VERSION 5.8 ;
BUSBITCHARS "[]" ;

UNITS
  DATABASE MICRONS 1000 ;
END UNITS

PROPERTYDEFINITIONS
  MACRO expanded_util REAL ;
  MACRO achieved_target_routing_density REAL ;
END PROPERTYDEFINITIONS

LAYER OVERLAP
  TYPE OVERLAP ;
END OVERLAP

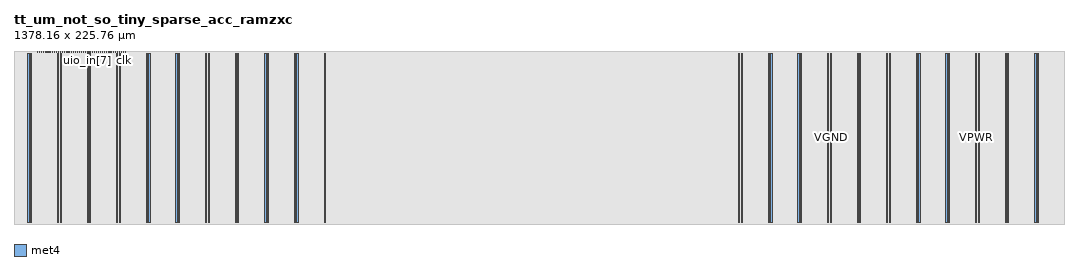
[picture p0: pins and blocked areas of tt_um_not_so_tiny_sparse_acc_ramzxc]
MACRO tt_um_not_so_tiny_sparse_acc_ramzxc
  CLASS BLOCK ;
  ORIGIN 0 0 ;
  SIZE 1378.16 BY 225.76 ;
  SYMMETRY X Y ;
  PIN ui_in[7]
    DIRECTION INPUT ;
    USE SIGNAL ;
    PORT
      LAYER met4 ;
        RECT 118.99 224.76 119.29 225.76 ;
    END
    ANTENNAPARTIALMETALAREA 0 ;
    ANTENNAPARTIALMETALSIDEAREA 0 ;
  END ui_in[7]
  PIN ui_in[6]
    DIRECTION INPUT ;
    USE SIGNAL ;
    PORT
      LAYER met4 ;
        RECT 121.75 224.76 122.05 225.76 ;
    END
    ANTENNAPARTIALMETALAREA 0 ;
    ANTENNAPARTIALMETALSIDEAREA 0 ;
  END ui_in[6]
  PIN ui_in[5]
    DIRECTION INPUT ;
    USE SIGNAL ;
    PORT
      LAYER met4 ;
        RECT 124.51 224.76 124.81 225.76 ;
    END
    ANTENNAPARTIALMETALAREA 0 ;
    ANTENNAPARTIALMETALSIDEAREA 0 ;
  END ui_in[5]
  PIN ui_in[4]
    DIRECTION INPUT ;
    USE SIGNAL ;
    PORT
      LAYER met4 ;
        RECT 127.27 224.76 127.57 225.76 ;
    END
    ANTENNAPARTIALMETALAREA 0 ;
    ANTENNAPARTIALMETALSIDEAREA 0 ;
  END ui_in[4]
  PIN ui_in[3]
    DIRECTION INPUT ;
    USE SIGNAL ;
    PORT
      LAYER met4 ;
        RECT 130.03 224.76 130.33 225.76 ;
    END
    ANTENNAPARTIALMETALAREA 0 ;
    ANTENNAPARTIALMETALSIDEAREA 0 ;
  END ui_in[3]
  PIN ui_in[2]
    DIRECTION INPUT ;
    USE SIGNAL ;
    PORT
      LAYER met4 ;
        RECT 132.79 224.76 133.09 225.76 ;
    END
    ANTENNAPARTIALMETALAREA 0 ;
    ANTENNAPARTIALMETALSIDEAREA 0 ;
  END ui_in[2]
  PIN ui_in[1]
    DIRECTION INPUT ;
    USE SIGNAL ;
    PORT
      LAYER met4 ;
        RECT 135.55 224.76 135.85 225.76 ;
    END
    ANTENNAPARTIALMETALAREA 0 ;
    ANTENNAPARTIALMETALSIDEAREA 0 ;
  END ui_in[1]
  PIN ui_in[0]
    DIRECTION INPUT ;
    USE SIGNAL ;
    PORT
      LAYER met4 ;
        RECT 138.31 224.76 138.61 225.76 ;
    END
    ANTENNAPARTIALMETALAREA 0 ;
    ANTENNAPARTIALMETALSIDEAREA 0 ;
  END ui_in[0]
  PIN uo_out[7]
    DIRECTION OUTPUT ;
    USE SIGNAL ;
    PORT
      LAYER met4 ;
        RECT 74.83 224.76 75.13 225.76 ;
    END
    ANTENNAPARTIALMETALAREA 0 ;
    ANTENNAPARTIALMETALSIDEAREA 0 ;
  END uo_out[7]
  PIN uo_out[6]
    DIRECTION OUTPUT ;
    USE SIGNAL ;
    PORT
      LAYER met4 ;
        RECT 77.59 224.76 77.89 225.76 ;
    END
    ANTENNAPARTIALMETALAREA 0 ;
    ANTENNAPARTIALMETALSIDEAREA 0 ;
  END uo_out[6]
  PIN uo_out[5]
    DIRECTION OUTPUT ;
    USE SIGNAL ;
    PORT
      LAYER met4 ;
        RECT 80.35 224.76 80.65 225.76 ;
    END
    ANTENNAPARTIALMETALAREA 0 ;
    ANTENNAPARTIALMETALSIDEAREA 0 ;
  END uo_out[5]
  PIN uo_out[4]
    DIRECTION OUTPUT ;
    USE SIGNAL ;
    PORT
      LAYER met4 ;
        RECT 83.11 224.76 83.41 225.76 ;
    END
    ANTENNAPARTIALMETALAREA 0 ;
    ANTENNAPARTIALMETALSIDEAREA 0 ;
  END uo_out[4]
  PIN uo_out[3]
    DIRECTION OUTPUT ;
    USE SIGNAL ;
    PORT
      LAYER met4 ;
        RECT 85.87 224.76 86.17 225.76 ;
    END
    ANTENNAPARTIALMETALAREA 0 ;
    ANTENNAPARTIALMETALSIDEAREA 0 ;
  END uo_out[3]
  PIN uo_out[2]
    DIRECTION OUTPUT ;
    USE SIGNAL ;
    PORT
      LAYER met4 ;
        RECT 88.63 224.76 88.93 225.76 ;
    END
    ANTENNAPARTIALMETALAREA 0 ;
    ANTENNAPARTIALMETALSIDEAREA 0 ;
  END uo_out[2]
  PIN uo_out[1]
    DIRECTION OUTPUT ;
    USE SIGNAL ;
    PORT
      LAYER met4 ;
        RECT 91.39 224.76 91.69 225.76 ;
    END
    ANTENNAPARTIALMETALAREA 0 ;
    ANTENNAPARTIALMETALSIDEAREA 0 ;
  END uo_out[1]
  PIN uo_out[0]
    DIRECTION OUTPUT ;
    USE SIGNAL ;
    PORT
      LAYER met4 ;
        RECT 94.15 224.76 94.45 225.76 ;
    END
    ANTENNAPARTIALMETALAREA 0 ;
    ANTENNAPARTIALMETALSIDEAREA 0 ;
  END uo_out[0]
  PIN uio_in[7]
    DIRECTION INPUT ;
    USE SIGNAL ;
    PORT
      LAYER met4 ;
        RECT 96.91 224.76 97.21 225.76 ;
    END
    ANTENNAPARTIALMETALAREA 0 ;
    ANTENNAPARTIALMETALSIDEAREA 0 ;
  END uio_in[7]
  PIN uio_in[6]
    DIRECTION INPUT ;
    USE SIGNAL ;
    PORT
      LAYER met4 ;
        RECT 99.67 224.76 99.97 225.76 ;
    END
    ANTENNAPARTIALMETALAREA 0 ;
    ANTENNAPARTIALMETALSIDEAREA 0 ;
  END uio_in[6]
  PIN uio_in[5]
    DIRECTION INPUT ;
    USE SIGNAL ;
    PORT
      LAYER met4 ;
        RECT 102.43 224.76 102.73 225.76 ;
    END
    ANTENNAPARTIALMETALAREA 0 ;
    ANTENNAPARTIALMETALSIDEAREA 0 ;
  END uio_in[5]
  PIN uio_in[4]
    DIRECTION INPUT ;
    USE SIGNAL ;
    PORT
      LAYER met4 ;
        RECT 105.19 224.76 105.49 225.76 ;
    END
    ANTENNAPARTIALMETALAREA 0 ;
    ANTENNAPARTIALMETALSIDEAREA 0 ;
  END uio_in[4]
  PIN uio_in[3]
    DIRECTION INPUT ;
    USE SIGNAL ;
    PORT
      LAYER met4 ;
        RECT 107.95 224.76 108.25 225.76 ;
    END
    ANTENNAPARTIALMETALAREA 0 ;
    ANTENNAPARTIALMETALSIDEAREA 0 ;
  END uio_in[3]
  PIN uio_in[2]
    DIRECTION INPUT ;
    USE SIGNAL ;
    PORT
      LAYER met4 ;
        RECT 110.71 224.76 111.01 225.76 ;
    END
    ANTENNAPARTIALMETALAREA 0 ;
    ANTENNAPARTIALMETALSIDEAREA 0 ;
  END uio_in[2]
  PIN uio_in[1]
    DIRECTION INPUT ;
    USE SIGNAL ;
    PORT
      LAYER met4 ;
        RECT 113.47 224.76 113.77 225.76 ;
    END
    ANTENNAPARTIALMETALAREA 0 ;
    ANTENNAPARTIALMETALSIDEAREA 0 ;
  END uio_in[1]
  PIN uio_in[0]
    DIRECTION INPUT ;
    USE SIGNAL ;
    PORT
      LAYER met4 ;
        RECT 116.23 224.76 116.53 225.76 ;
    END
    ANTENNAPARTIALMETALAREA 0 ;
    ANTENNAPARTIALMETALSIDEAREA 0 ;
  END uio_in[0]
  PIN uio_out[7]
    DIRECTION OUTPUT ;
    USE SIGNAL ;
    PORT
      LAYER met4 ;
        RECT 52.75 224.76 53.05 225.76 ;
    END
    ANTENNAPARTIALMETALAREA 0 ;
    ANTENNAPARTIALMETALSIDEAREA 0 ;
  END uio_out[7]
  PIN uio_out[6]
    DIRECTION OUTPUT ;
    USE SIGNAL ;
    PORT
      LAYER met4 ;
        RECT 55.51 224.76 55.81 225.76 ;
    END
    ANTENNAPARTIALMETALAREA 0 ;
    ANTENNAPARTIALMETALSIDEAREA 0 ;
  END uio_out[6]
  PIN uio_out[5]
    DIRECTION OUTPUT ;
    USE SIGNAL ;
    PORT
      LAYER met4 ;
        RECT 58.27 224.76 58.57 225.76 ;
    END
    ANTENNAPARTIALMETALAREA 0 ;
    ANTENNAPARTIALMETALSIDEAREA 0 ;
  END uio_out[5]
  PIN uio_out[4]
    DIRECTION OUTPUT ;
    USE SIGNAL ;
    PORT
      LAYER met4 ;
        RECT 61.03 224.76 61.33 225.76 ;
    END
    ANTENNAPARTIALMETALAREA 0 ;
    ANTENNAPARTIALMETALSIDEAREA 0 ;
  END uio_out[4]
  PIN uio_out[3]
    DIRECTION OUTPUT ;
    USE SIGNAL ;
    PORT
      LAYER met4 ;
        RECT 63.79 224.76 64.09 225.76 ;
    END
    ANTENNAPARTIALMETALAREA 0 ;
    ANTENNAPARTIALMETALSIDEAREA 0 ;
  END uio_out[3]
  PIN uio_out[2]
    DIRECTION OUTPUT ;
    USE SIGNAL ;
    PORT
      LAYER met4 ;
        RECT 66.55 224.76 66.85 225.76 ;
    END
    ANTENNAPARTIALMETALAREA 0 ;
    ANTENNAPARTIALMETALSIDEAREA 0 ;
  END uio_out[2]
  PIN uio_out[1]
    DIRECTION OUTPUT ;
    USE SIGNAL ;
    PORT
      LAYER met4 ;
        RECT 69.31 224.76 69.61 225.76 ;
    END
    ANTENNAPARTIALMETALAREA 0 ;
    ANTENNAPARTIALMETALSIDEAREA 0 ;
  END uio_out[1]
  PIN uio_out[0]
    DIRECTION OUTPUT ;
    USE SIGNAL ;
    PORT
      LAYER met4 ;
        RECT 72.07 224.76 72.37 225.76 ;
    END
    ANTENNAPARTIALMETALAREA 0 ;
    ANTENNAPARTIALMETALSIDEAREA 0 ;
  END uio_out[0]
  PIN uio_oe[7]
    DIRECTION OUTPUT ;
    USE SIGNAL ;
    PORT
      LAYER met4 ;
        RECT 30.67 224.76 30.97 225.76 ;
    END
    ANTENNAPARTIALMETALAREA 0 ;
    ANTENNAPARTIALMETALSIDEAREA 0 ;
  END uio_oe[7]
  PIN uio_oe[6]
    DIRECTION OUTPUT ;
    USE SIGNAL ;
    PORT
      LAYER met4 ;
        RECT 33.43 224.76 33.73 225.76 ;
    END
    ANTENNAPARTIALMETALAREA 0 ;
    ANTENNAPARTIALMETALSIDEAREA 0 ;
  END uio_oe[6]
  PIN uio_oe[5]
    DIRECTION OUTPUT ;
    USE SIGNAL ;
    PORT
      LAYER met4 ;
        RECT 36.19 224.76 36.49 225.76 ;
    END
    ANTENNAPARTIALMETALAREA 0 ;
    ANTENNAPARTIALMETALSIDEAREA 0 ;
  END uio_oe[5]
  PIN uio_oe[4]
    DIRECTION OUTPUT ;
    USE SIGNAL ;
    PORT
      LAYER met4 ;
        RECT 38.95 224.76 39.25 225.76 ;
    END
    ANTENNAPARTIALMETALAREA 0 ;
    ANTENNAPARTIALMETALSIDEAREA 0 ;
  END uio_oe[4]
  PIN uio_oe[3]
    DIRECTION OUTPUT ;
    USE SIGNAL ;
    PORT
      LAYER met4 ;
        RECT 41.71 224.76 42.01 225.76 ;
    END
    ANTENNAPARTIALMETALAREA 0 ;
    ANTENNAPARTIALMETALSIDEAREA 0 ;
  END uio_oe[3]
  PIN uio_oe[2]
    DIRECTION OUTPUT ;
    USE SIGNAL ;
    PORT
      LAYER met4 ;
        RECT 44.47 224.76 44.77 225.76 ;
    END
    ANTENNAPARTIALMETALAREA 0 ;
    ANTENNAPARTIALMETALSIDEAREA 0 ;
  END uio_oe[2]
  PIN uio_oe[1]
    DIRECTION OUTPUT ;
    USE SIGNAL ;
    PORT
      LAYER met4 ;
        RECT 47.23 224.76 47.53 225.76 ;
    END
    ANTENNAPARTIALMETALAREA 0 ;
    ANTENNAPARTIALMETALSIDEAREA 0 ;
  END uio_oe[1]
  PIN uio_oe[0]
    DIRECTION OUTPUT ;
    USE SIGNAL ;
    PORT
      LAYER met4 ;
        RECT 49.99 224.76 50.29 225.76 ;
    END
    ANTENNAPARTIALMETALAREA 0 ;
    ANTENNAPARTIALMETALSIDEAREA 0 ;
  END uio_oe[0]
  PIN ena
    DIRECTION INPUT ;
    USE SIGNAL ;
    PORT
      LAYER met4 ;
        RECT 146.59 224.76 146.89 225.76 ;
    END
    ANTENNAPARTIALMETALAREA 0 ;
    ANTENNAPARTIALMETALSIDEAREA 0 ;
  END ena
  PIN clk
    DIRECTION INPUT ;
    USE CLOCK ;
    PORT
      LAYER met4 ;
        RECT 143.83 224.76 144.13 225.76 ;
    END
    ANTENNAPARTIALMETALAREA 0 ;
    ANTENNAPARTIALMETALSIDEAREA 0 ;
  END clk
  PIN rst_n
    DIRECTION INPUT ;
    USE SIGNAL ;
    PORT
      LAYER met4 ;
        RECT 141.07 224.76 141.37 225.76 ;
    END
    ANTENNAPARTIALMETALAREA 0 ;
    ANTENNAPARTIALMETALSIDEAREA 0 ;
  END rst_n
  PIN VPWR
    DIRECTION INPUT ;
    USE POWER ;
    PORT
      LAYER met4 ;
        RECT 18.28 2.48 19.88 223.28 ;
        RECT 57.15 2.48 58.75 223.28 ;
        RECT 96.02 2.48 97.62 223.28 ;
        RECT 134.89 2.48 136.49 223.28 ;
        RECT 173.76 2.48 175.36 223.28 ;
        RECT 212.63 2.48 214.23 223.28 ;
        RECT 251.5 2.48 253.1 223.28 ;
        RECT 290.37 2.48 291.97 223.28 ;
        RECT 329.24 2.48 330.84 223.28 ;
        RECT 368.11 2.48 369.71 223.28 ;
        RECT 406.98 2.48 408.58 223.28 ;
        RECT 951.16 2.48 952.76 223.28 ;
        RECT 990.03 2.48 991.63 223.28 ;
        RECT 1028.9 2.48 1030.5 223.28 ;
        RECT 1067.77 2.48 1069.37 223.28 ;
        RECT 1106.64 2.48 1108.24 223.28 ;
        RECT 1145.51 2.48 1147.11 223.28 ;
        RECT 1184.38 2.48 1185.98 223.28 ;
        RECT 1223.25 2.48 1224.85 223.28 ;
        RECT 1262.12 2.48 1263.72 223.28 ;
        RECT 1300.99 2.48 1302.59 223.28 ;
        RECT 1339.86 2.48 1341.46 223.28 ;
    END
    ANTENNAPARTIALMETALAREA 0 ;
    ANTENNAPARTIALMETALSIDEAREA 0 ;
  END VPWR
  PIN VGND
    DIRECTION INPUT ;
    USE GROUND ;
    PORT
      LAYER met4 ;
        RECT 21.58 2.48 23.18 223.28 ;
        RECT 60.45 2.48 62.05 223.28 ;
        RECT 99.32 2.48 100.92 223.28 ;
        RECT 138.19 2.48 139.79 223.28 ;
        RECT 177.06 2.48 178.66 223.28 ;
        RECT 215.93 2.48 217.53 223.28 ;
        RECT 254.8 2.48 256.4 223.28 ;
        RECT 293.67 2.48 295.27 223.28 ;
        RECT 332.54 2.48 334.14 223.28 ;
        RECT 371.41 2.48 373.01 223.28 ;
        RECT 954.46 2.48 956.06 223.28 ;
        RECT 993.33 2.48 994.93 223.28 ;
        RECT 1032.2 2.48 1033.8 223.28 ;
        RECT 1071.07 2.48 1072.67 223.28 ;
        RECT 1109.94 2.48 1111.54 223.28 ;
        RECT 1148.81 2.48 1150.41 223.28 ;
        RECT 1187.68 2.48 1189.28 223.28 ;
        RECT 1226.55 2.48 1228.15 223.28 ;
        RECT 1265.42 2.48 1267.02 223.28 ;
        RECT 1304.29 2.48 1305.89 223.28 ;
        RECT 1343.16 2.48 1344.76 223.28 ;
    END
    ANTENNAPARTIALMETALAREA 0 ;
    ANTENNAPARTIALMETALSIDEAREA 0 ;
  END VGND
  OBS
    LAYER li1 ;
      RECT 331.2 0 629.28 225.76 ;
      RECT 11.96 0 310.04 225.76 ;
    LAYER li1 SPACING 0 ;
      RECT 0 0 1378.16 225.76 ;
    LAYER met1 SPACING 0 ;
      RECT 0 0 1378.16 225.76 ;
    LAYER met2 SPACING 0 ;
      RECT 0 0 1378.16 225.76 ;
    LAYER met3 SPACING 0 ;
      RECT 0 0 1378.16 225.76 ;
    LAYER met4 SPACING 0 ;
      POLYGON 1378.16 225.76 1378.16 223.28 18.28 223.28 18.28 2.48 19.88 2.48 19.88 223.28 21.58 223.28 21.58 2.48 23.18 2.48 23.18 223.28 57.15 223.28 57.15 2.48 58.75 2.48 58.75 223.28 60.45 223.28 60.45 2.48 62.05 2.48 62.05 223.28 96.02 223.28 96.02 2.48 97.62 2.48 97.62 223.28 99.32 223.28 99.32 2.48 100.92 2.48 100.92 223.28 134.89 223.28 134.89 2.48 136.49 2.48 136.49 223.28 138.19 223.28 138.19 2.48 139.79 2.48 139.79 223.28 173.76 223.28 173.76 2.48 175.36 2.48 175.36 223.28 177.06 223.28 177.06 2.48 178.66 2.48 178.66 223.28 212.63 223.28 212.63 2.48 214.23 2.48 214.23 223.28 215.93 223.28 215.93 2.48 217.53 2.48 217.53 223.28 251.5 223.28 251.5 2.48 253.1 2.48 253.1 223.28 254.8 223.28 254.8 2.48 256.4 2.48 256.4 223.28 290.37 223.28 290.37 2.48 291.97 2.48 291.97 223.28 293.67 223.28 293.67 2.48 295.27 2.48 295.27 223.28 329.24 223.28 329.24 2.48 330.84 2.48 330.84 223.28 332.54 223.28 332.54 2.48 334.14 2.48 334.14 223.28 368.11 223.28 368.11 2.48 369.71 2.48 369.71 223.28 371.41 223.28 371.41 2.48 373.01 2.48 373.01 223.28 406.98 223.28 406.98 2.48 408.58 2.48 408.58 223.28 951.16 223.28 951.16 2.48 952.76 2.48 952.76 223.28 954.46 223.28 954.46 2.48 956.06 2.48 956.06 223.28 990.03 223.28 990.03 2.48 991.63 2.48 991.63 223.28 993.33 223.28 993.33 2.48 994.93 2.48 994.93 223.28 1028.9 223.28 1028.9 2.48 1030.5 2.48 1030.5 223.28 1032.2 223.28 1032.2 2.48 1033.8 2.48 1033.8 223.28 1067.77 223.28 1067.77 2.48 1069.37 2.48 1069.37 223.28 1071.07 223.28 1071.07 2.48 1072.67 2.48 1072.67 223.28 1106.64 223.28 1106.64 2.48 1108.24 2.48 1108.24 223.28 1109.94 223.28 1109.94 2.48 1111.54 2.48 1111.54 223.28 1145.51 223.28 1145.51 2.48 1147.11 2.48 1147.11 223.28 1148.81 223.28 1148.81 2.48 1150.41 2.48 1150.41 223.28 1184.38 223.28 1184.38 2.48 1185.98 2.48 1185.98 223.28 1187.68 223.28 1187.68 2.48 1189.28 2.48 1189.28 223.28 1223.25 223.28 1223.25 2.48 1224.85 2.48 1224.85 223.28 1226.55 223.28 1226.55 2.48 1228.15 2.48 1228.15 223.28 1262.12 223.28 1262.12 2.48 1263.72 2.48 1263.72 223.28 1265.42 223.28 1265.42 2.48 1267.02 2.48 1267.02 223.28 1300.99 223.28 1300.99 2.48 1302.59 2.48 1302.59 223.28 1304.29 223.28 1304.29 2.48 1305.89 2.48 1305.89 223.28 1339.86 223.28 1339.86 2.48 1341.46 2.48 1341.46 223.28 1343.16 223.28 1343.16 2.48 1344.76 2.48 1344.76 223.28 1378.16 223.28 1378.16 0 0 0 0 225.76 30.67 225.76 30.67 224.76 30.97 224.76 30.97 225.76 33.43 225.76 33.43 224.76 33.73 224.76 33.73 225.76 36.19 225.76 36.19 224.76 36.49 224.76 36.49 225.76 38.95 225.76 38.95 224.76 39.25 224.76 39.25 225.76 41.71 225.76 41.71 224.76 42.01 224.76 42.01 225.76 44.47 225.76 44.47 224.76 44.77 224.76 44.77 225.76 47.23 225.76 47.23 224.76 47.53 224.76 47.53 225.76 49.99 225.76 49.99 224.76 50.29 224.76 50.29 225.76 52.75 225.76 52.75 224.76 53.05 224.76 53.05 225.76 55.51 225.76 55.51 224.76 55.81 224.76 55.81 225.76 58.27 225.76 58.27 224.76 58.57 224.76 58.57 225.76 61.03 225.76 61.03 224.76 61.33 224.76 61.33 225.76 63.79 225.76 63.79 224.76 64.09 224.76 64.09 225.76 66.55 225.76 66.55 224.76 66.85 224.76 66.85 225.76 69.31 225.76 69.31 224.76 69.61 224.76 69.61 225.76 72.07 225.76 72.07 224.76 72.37 224.76 72.37 225.76 74.83 225.76 74.83 224.76 75.13 224.76 75.13 225.76 77.59 225.76 77.59 224.76 77.89 224.76 77.89 225.76 80.35 225.76 80.35 224.76 80.65 224.76 80.65 225.76 83.11 225.76 83.11 224.76 83.41 224.76 83.41 225.76 85.87 225.76 85.87 224.76 86.17 224.76 86.17 225.76 88.63 225.76 88.63 224.76 88.93 224.76 88.93 225.76 91.39 225.76 91.39 224.76 91.69 224.76 91.69 225.76 94.15 225.76 94.15 224.76 94.45 224.76 94.45 225.76 96.91 225.76 96.91 224.76 97.21 224.76 97.21 225.76 99.67 225.76 99.67 224.76 99.97 224.76 99.97 225.76 102.43 225.76 102.43 224.76 102.73 224.76 102.73 225.76 105.19 225.76 105.19 224.76 105.49 224.76 105.49 225.76 107.95 225.76 107.95 224.76 108.25 224.76 108.25 225.76 110.71 225.76 110.71 224.76 111.01 224.76 111.01 225.76 113.47 225.76 113.47 224.76 113.77 224.76 113.77 225.76 116.23 225.76 116.23 224.76 116.53 224.76 116.53 225.76 118.99 225.76 118.99 224.76 119.29 224.76 119.29 225.76 121.75 225.76 121.75 224.76 122.05 224.76 122.05 225.76 124.51 225.76 124.51 224.76 124.81 224.76 124.81 225.76 127.27 225.76 127.27 224.76 127.57 224.76 127.57 225.76 130.03 225.76 130.03 224.76 130.33 224.76 130.33 225.76 132.79 225.76 132.79 224.76 133.09 224.76 133.09 225.76 135.55 225.76 135.55 224.76 135.85 224.76 135.85 225.76 138.31 225.76 138.31 224.76 138.61 224.76 138.61 225.76 141.07 225.76 141.07 224.76 141.37 224.76 141.37 225.76 143.83 225.76 143.83 224.76 144.13 224.76 144.13 225.76 146.59 225.76 146.59 224.76 146.89 224.76 146.89 225.76 ;
    LAYER nwell SPACING 0 ;
      RECT 0 0 1378.16 225.76 ;
    LAYER pwell SPACING 0 ;
      RECT 0 0 1378.16 225.76 ;
    LAYER met4 ;
      POLYGON 61.75 224.91 61.75 224.59 62.67 224.59 62.67 221.205 62.685 221.205 62.685 220.875 62.355 220.875 62.355 221.205 62.37 221.205 62.37 224.29 61.45 224.29 61.45 224.36 61.73 224.36 61.73 224.91 ;
      RECT 1069.755 193.675 1070.085 194.005 ;
      RECT 1069.755 190.955 1070.085 191.285 ;
      POLYGON 1151.045 178.365 1151.045 178.035 1151.03 178.035 1151.03 142.325 1151.045 142.325 1151.045 141.995 1150.715 141.995 1150.715 142.325 1150.73 142.325 1150.73 178.035 1150.715 178.035 1150.715 178.365 ;
      RECT 1069.755 173.275 1070.085 173.605 ;
      RECT 1069.755 171.915 1070.085 172.245 ;
      POLYGON 1151.045 136.885 1151.045 136.555 1151.03 136.555 1151.03 115.805 1151.045 115.805 1151.045 115.475 1150.715 115.475 1150.715 115.805 1150.73 115.805 1150.73 136.555 1150.715 136.555 1150.715 136.885 ;
      POLYGON 995.565 136.885 995.565 136.87 998.31 136.87 998.31 136.57 995.565 136.57 995.565 136.555 995.235 136.555 995.235 136.885 ;
      POLYGON 1151.045 98.805 1151.045 98.475 1151.03 98.475 1151.03 88.605 1151.045 88.605 1151.045 88.275 1150.715 88.275 1150.715 88.605 1150.73 88.605 1150.73 98.475 1150.715 98.475 1150.715 98.805 ;
      POLYGON 1377.76 225.36 1377.76 223.68 17.88 223.68 17.88 2.08 20.28 2.08 20.28 223.68 21.18 223.68 21.18 2.08 23.58 2.08 23.58 223.68 56.75 223.68 56.75 2.08 59.15 2.08 59.15 223.68 60.05 223.68 60.05 2.08 62.45 2.08 62.45 223.68 95.62 223.68 95.62 2.08 98.02 2.08 98.02 223.68 98.92 223.68 98.92 2.08 101.32 2.08 101.32 223.68 134.49 223.68 134.49 2.08 136.89 2.08 136.89 223.68 137.79 223.68 137.79 2.08 140.19 2.08 140.19 223.68 173.36 223.68 173.36 2.08 175.76 2.08 175.76 223.68 176.66 223.68 176.66 2.08 179.06 2.08 179.06 223.68 212.23 223.68 212.23 2.08 214.63 2.08 214.63 223.68 215.53 223.68 215.53 2.08 217.93 2.08 217.93 223.68 251.1 223.68 251.1 2.08 253.5 2.08 253.5 223.68 254.4 223.68 254.4 2.08 256.8 2.08 256.8 223.68 289.97 223.68 289.97 2.08 292.37 2.08 292.37 223.68 293.27 223.68 293.27 2.08 295.67 2.08 295.67 223.68 328.84 223.68 328.84 2.08 331.24 2.08 331.24 223.68 332.14 223.68 332.14 2.08 334.54 2.08 334.54 223.68 367.71 223.68 367.71 2.08 370.11 2.08 370.11 223.68 371.01 223.68 371.01 2.08 373.41 2.08 373.41 223.68 406.58 223.68 406.58 2.08 408.98 2.08 408.98 223.68 950.76 223.68 950.76 2.08 953.16 2.08 953.16 223.68 954.06 223.68 954.06 2.08 956.46 2.08 956.46 223.68 989.63 223.68 989.63 2.08 992.03 2.08 992.03 223.68 992.93 223.68 992.93 2.08 995.33 2.08 995.33 223.68 1028.5 223.68 1028.5 2.08 1030.9 2.08 1030.9 223.68 1031.8 223.68 1031.8 2.08 1034.2 2.08 1034.2 223.68 1067.37 223.68 1067.37 2.08 1069.77 2.08 1069.77 223.68 1070.67 223.68 1070.67 2.08 1073.07 2.08 1073.07 223.68 1106.24 223.68 1106.24 2.08 1108.64 2.08 1108.64 223.68 1109.54 223.68 1109.54 2.08 1111.94 2.08 1111.94 223.68 1145.11 223.68 1145.11 2.08 1147.51 2.08 1147.51 223.68 1148.41 223.68 1148.41 2.08 1150.81 2.08 1150.81 223.68 1183.98 223.68 1183.98 2.08 1186.38 2.08 1186.38 223.68 1187.28 223.68 1187.28 2.08 1189.68 2.08 1189.68 223.68 1222.85 223.68 1222.85 2.08 1225.25 2.08 1225.25 223.68 1226.15 223.68 1226.15 2.08 1228.55 2.08 1228.55 223.68 1261.72 223.68 1261.72 2.08 1264.12 2.08 1264.12 223.68 1265.02 223.68 1265.02 2.08 1267.42 2.08 1267.42 223.68 1300.59 223.68 1300.59 2.08 1302.99 2.08 1302.99 223.68 1303.89 223.68 1303.89 2.08 1306.29 2.08 1306.29 223.68 1339.46 223.68 1339.46 2.08 1341.86 2.08 1341.86 223.68 1342.76 223.68 1342.76 2.08 1345.16 2.08 1345.16 223.68 1377.76 223.68 1377.76 0.4 0.4 0.4 0.4 225.36 30.27 225.36 30.27 224.36 31.37 224.36 31.37 225.36 33.03 225.36 33.03 224.36 34.13 224.36 34.13 225.36 35.79 225.36 35.79 224.36 36.89 224.36 36.89 225.36 38.55 225.36 38.55 224.36 39.65 224.36 39.65 225.36 41.31 225.36 41.31 224.36 42.41 224.36 42.41 225.36 44.07 225.36 44.07 224.36 45.17 224.36 45.17 225.36 46.83 225.36 46.83 224.36 47.93 224.36 47.93 225.36 49.59 225.36 49.59 224.36 50.69 224.36 50.69 225.36 52.35 225.36 52.35 224.36 53.45 224.36 53.45 225.36 55.11 225.36 55.11 224.36 56.21 224.36 56.21 225.36 57.87 225.36 57.87 224.36 58.97 224.36 58.97 225.36 60.63 225.36 60.63 224.36 61.73 224.36 61.73 225.36 63.39 225.36 63.39 224.36 64.49 224.36 64.49 225.36 66.15 225.36 66.15 224.36 67.25 224.36 67.25 225.36 68.91 225.36 68.91 224.36 70.01 224.36 70.01 225.36 71.67 225.36 71.67 224.36 72.77 224.36 72.77 225.36 74.43 225.36 74.43 224.36 75.53 224.36 75.53 225.36 77.19 225.36 77.19 224.36 78.29 224.36 78.29 225.36 79.95 225.36 79.95 224.36 81.05 224.36 81.05 225.36 82.71 225.36 82.71 224.36 83.81 224.36 83.81 225.36 85.47 225.36 85.47 224.36 86.57 224.36 86.57 225.36 88.23 225.36 88.23 224.36 89.33 224.36 89.33 225.36 90.99 225.36 90.99 224.36 92.09 224.36 92.09 225.36 93.75 225.36 93.75 224.36 94.85 224.36 94.85 225.36 96.51 225.36 96.51 224.36 97.61 224.36 97.61 225.36 99.27 225.36 99.27 224.36 100.37 224.36 100.37 225.36 102.03 225.36 102.03 224.36 103.13 224.36 103.13 225.36 104.79 225.36 104.79 224.36 105.89 224.36 105.89 225.36 107.55 225.36 107.55 224.36 108.65 224.36 108.65 225.36 110.31 225.36 110.31 224.36 111.41 224.36 111.41 225.36 113.07 225.36 113.07 224.36 114.17 224.36 114.17 225.36 115.83 225.36 115.83 224.36 116.93 224.36 116.93 225.36 118.59 225.36 118.59 224.36 119.69 224.36 119.69 225.36 121.35 225.36 121.35 224.36 122.45 224.36 122.45 225.36 124.11 225.36 124.11 224.36 125.21 224.36 125.21 225.36 126.87 225.36 126.87 224.36 127.97 224.36 127.97 225.36 129.63 225.36 129.63 224.36 130.73 224.36 130.73 225.36 132.39 225.36 132.39 224.36 133.49 224.36 133.49 225.36 135.15 225.36 135.15 224.36 136.25 224.36 136.25 225.36 137.91 225.36 137.91 224.36 139.01 224.36 139.01 225.36 140.67 225.36 140.67 224.36 141.77 224.36 141.77 225.36 143.43 225.36 143.43 224.36 144.53 224.36 144.53 225.36 146.19 225.36 146.19 224.36 147.29 224.36 147.29 225.36 ;
    LAYER li1 ;
      RECT 0.34 0.34 1377.82 225.42 ;
    LAYER met1 ;
      RECT 629.28 220.12 1378.16 220.6 ;
      RECT 0 220.12 305.44 220.6 ;
      RECT 629.28 217.4 1378.16 217.88 ;
      RECT 0 217.4 305.44 217.88 ;
      RECT 629.28 214.68 1378.16 215.16 ;
      RECT 0 214.68 13.8 215.16 ;
      RECT 629.28 211.96 1378.16 212.44 ;
      RECT 0 211.96 13.8 212.44 ;
      RECT 629.28 209.24 1378.16 209.72 ;
      RECT 0 209.24 13.8 209.72 ;
      RECT 629.28 206.52 1378.16 207 ;
      RECT 0 206.52 13.8 207 ;
      RECT 629.28 203.8 1378.16 204.28 ;
      RECT 0 203.8 13.8 204.28 ;
      RECT 629.28 201.08 1378.16 201.56 ;
      RECT 0 201.08 13.8 201.56 ;
      RECT 629.28 198.36 1378.16 198.84 ;
      RECT 0 198.36 13.8 198.84 ;
      RECT 629.28 195.64 1378.16 196.12 ;
      RECT 0 195.64 13.8 196.12 ;
      RECT 629.28 192.92 1378.16 193.4 ;
      RECT 0 192.92 13.8 193.4 ;
      RECT 629.28 190.2 1378.16 190.68 ;
      RECT 0 190.2 13.8 190.68 ;
      RECT 629.28 187.48 1378.16 187.96 ;
      RECT 0 187.48 13.8 187.96 ;
      RECT 629.28 184.76 1378.16 185.24 ;
      RECT 0 184.76 13.8 185.24 ;
      RECT 629.28 182.04 1378.16 182.52 ;
      RECT 0 182.04 13.8 182.52 ;
      RECT 629.28 179.32 1378.16 179.8 ;
      RECT 0 179.32 13.8 179.8 ;
      RECT 629.28 176.6 1378.16 177.08 ;
      RECT 0 176.6 13.8 177.08 ;
      RECT 629.28 173.88 1378.16 174.36 ;
      RECT 0 173.88 13.8 174.36 ;
      RECT 629.28 171.16 1378.16 171.64 ;
      RECT 0 171.16 13.8 171.64 ;
      RECT 629.28 168.44 1378.16 168.92 ;
      RECT 0 168.44 13.8 168.92 ;
      RECT 629.28 165.72 1378.16 166.2 ;
      RECT 0 165.72 13.8 166.2 ;
      RECT 629.28 163 1378.16 163.48 ;
      RECT 0 163 13.8 163.48 ;
      RECT 629.28 160.28 1378.16 160.76 ;
      RECT 0 160.28 13.8 160.76 ;
      RECT 629.28 157.56 1378.16 158.04 ;
      RECT 0 157.56 13.8 158.04 ;
      RECT 629.28 154.84 1378.16 155.32 ;
      RECT 0 154.84 13.8 155.32 ;
      RECT 629.28 152.12 1378.16 152.6 ;
      RECT 0 152.12 13.8 152.6 ;
      RECT 629.28 149.4 1378.16 149.88 ;
      RECT 0 149.4 13.8 149.88 ;
      RECT 629.28 146.68 1378.16 147.16 ;
      RECT 0 146.68 13.8 147.16 ;
      RECT 629.28 143.96 1378.16 144.44 ;
      RECT 0 143.96 13.8 144.44 ;
      RECT 629.28 141.24 1378.16 141.72 ;
      RECT 0 141.24 13.8 141.72 ;
      RECT 629.28 138.52 1378.16 139 ;
      RECT 0 138.52 13.8 139 ;
      RECT 629.28 135.8 1378.16 136.28 ;
      RECT 0 135.8 13.8 136.28 ;
      RECT 629.28 133.08 1378.16 133.56 ;
      RECT 0 133.08 13.8 133.56 ;
      RECT 629.28 130.36 1378.16 130.84 ;
      RECT 0 130.36 13.8 130.84 ;
      RECT 629.28 127.64 1378.16 128.12 ;
      RECT 0 127.64 13.8 128.12 ;
      RECT 629.28 124.92 1378.16 125.4 ;
      RECT 0 124.92 13.8 125.4 ;
      RECT 629.28 122.2 1378.16 122.68 ;
      RECT 0 122.2 13.8 122.68 ;
      RECT 629.28 119.48 1378.16 119.96 ;
      RECT 0 119.48 13.8 119.96 ;
      RECT 629.28 116.76 1378.16 117.24 ;
      RECT 0 116.76 13.8 117.24 ;
      RECT 629.28 114.04 1378.16 114.52 ;
      RECT 0 114.04 13.8 114.52 ;
      RECT 629.28 111.32 1378.16 111.8 ;
      RECT 0 111.32 13.8 111.8 ;
      RECT 629.28 108.6 1378.16 109.08 ;
      RECT 0 108.6 13.8 109.08 ;
      RECT 629.28 105.88 1378.16 106.36 ;
      RECT 0 105.88 13.8 106.36 ;
      RECT 629.28 103.16 1378.16 103.64 ;
      RECT 0 103.16 13.8 103.64 ;
      RECT 629.28 100.44 1378.16 100.92 ;
      RECT 0 100.44 13.8 100.92 ;
      RECT 629.28 97.72 1378.16 98.2 ;
      RECT 0 97.72 13.8 98.2 ;
      RECT 629.28 95 1378.16 95.48 ;
      RECT 0 95 13.8 95.48 ;
      RECT 629.28 92.28 1378.16 92.76 ;
      RECT 0 92.28 13.8 92.76 ;
      RECT 629.28 89.56 1378.16 90.04 ;
      RECT 0 89.56 13.8 90.04 ;
      RECT 629.28 86.84 1378.16 87.32 ;
      RECT 0 86.84 13.8 87.32 ;
      RECT 629.28 84.12 1378.16 84.6 ;
      RECT 0 84.12 13.8 84.6 ;
      RECT 629.28 81.4 1378.16 81.88 ;
      RECT 0 81.4 13.8 81.88 ;
      RECT 629.28 78.68 1378.16 79.16 ;
      RECT 0 78.68 13.8 79.16 ;
      RECT 629.28 75.96 1378.16 76.44 ;
      RECT 0 75.96 13.8 76.44 ;
      RECT 629.28 73.24 1378.16 73.72 ;
      RECT 0 73.24 13.8 73.72 ;
      RECT 629.28 70.52 1378.16 71 ;
      RECT 0 70.52 13.8 71 ;
      RECT 629.28 67.8 1378.16 68.28 ;
      RECT 0 67.8 13.8 68.28 ;
      RECT 629.28 65.08 1378.16 65.56 ;
      RECT 0 65.08 13.8 65.56 ;
      RECT 629.28 62.36 1378.16 62.84 ;
      RECT 0 62.36 13.8 62.84 ;
      RECT 629.28 59.64 1378.16 60.12 ;
      RECT 0 59.64 13.8 60.12 ;
      RECT 629.28 56.92 1378.16 57.4 ;
      RECT 0 56.92 13.8 57.4 ;
      RECT 629.28 54.2 1378.16 54.68 ;
      RECT 0 54.2 13.8 54.68 ;
      RECT 629.28 51.48 1378.16 51.96 ;
      RECT 0 51.48 13.8 51.96 ;
      RECT 629.28 48.76 1378.16 49.24 ;
      RECT 0 48.76 13.8 49.24 ;
      RECT 629.28 46.04 1378.16 46.52 ;
      RECT 0 46.04 13.8 46.52 ;
      RECT 629.28 43.32 1378.16 43.8 ;
      RECT 0 43.32 13.8 43.8 ;
      RECT 629.28 40.6 1378.16 41.08 ;
      RECT 0 40.6 13.8 41.08 ;
      RECT 629.28 37.88 1378.16 38.36 ;
      RECT 0 37.88 13.8 38.36 ;
      RECT 629.28 35.16 1378.16 35.64 ;
      RECT 0 35.16 13.8 35.64 ;
      RECT 629.28 32.44 1378.16 32.92 ;
      RECT 0 32.44 13.8 32.92 ;
      RECT 629.28 29.72 1378.16 30.2 ;
      RECT 0 29.72 13.8 30.2 ;
      RECT 629.28 27 1378.16 27.48 ;
      RECT 0 27 13.8 27.48 ;
      RECT 629.28 24.28 1378.16 24.76 ;
      RECT 0 24.28 13.8 24.76 ;
      RECT 629.28 21.56 1378.16 22.04 ;
      RECT 0 21.56 13.8 22.04 ;
      RECT 629.28 18.84 1378.16 19.32 ;
      RECT 0 18.84 13.8 19.32 ;
      RECT 629.28 16.12 1378.16 16.6 ;
      RECT 0 16.12 13.8 16.6 ;
      RECT 629.28 13.4 1378.16 13.88 ;
      RECT 0 13.4 13.8 13.88 ;
      RECT 629.28 10.68 1378.16 11.16 ;
      RECT 0 10.68 13.8 11.16 ;
      RECT 629.28 7.96 1378.16 8.44 ;
      RECT 0 7.96 305.44 8.44 ;
      RECT 629.28 5.24 1378.16 5.72 ;
      RECT 0 5.24 305.44 5.72 ;
      RECT 629.28 2.52 1378.16 3 ;
      RECT 0 2.52 305.44 3 ;
      RECT 0.28 0.28 1377.88 225.48 ;
    LAYER met2 ;
      RECT 0.28 0.28 1377.88 225.48 ;
    LAYER met3 ;
      RECT 0.4 0.4 1377.76 225.36 ;
    LAYER via3 ;
      RECT 58.74 224.34 58.94 224.54 ;
      RECT 62.42 220.94 62.62 221.14 ;
      RECT 1150.78 178.1 1150.98 178.3 ;
      RECT 1344.46 170.66 1344.66 170.86 ;
      RECT 1344.06 170.66 1344.26 170.86 ;
      RECT 1343.66 170.66 1343.86 170.86 ;
      RECT 1343.26 170.66 1343.46 170.86 ;
      RECT 1305.59 170.66 1305.79 170.86 ;
      RECT 1305.19 170.66 1305.39 170.86 ;
      RECT 1304.79 170.66 1304.99 170.86 ;
      RECT 1304.39 170.66 1304.59 170.86 ;
      RECT 1266.72 170.66 1266.92 170.86 ;
      RECT 1266.32 170.66 1266.52 170.86 ;
      RECT 1265.92 170.66 1266.12 170.86 ;
      RECT 1265.52 170.66 1265.72 170.86 ;
      RECT 1227.85 170.66 1228.05 170.86 ;
      RECT 1227.45 170.66 1227.65 170.86 ;
      RECT 1227.05 170.66 1227.25 170.86 ;
      RECT 1226.65 170.66 1226.85 170.86 ;
      RECT 1188.98 170.66 1189.18 170.86 ;
      RECT 1188.58 170.66 1188.78 170.86 ;
      RECT 1188.18 170.66 1188.38 170.86 ;
      RECT 1187.78 170.66 1187.98 170.86 ;
      RECT 1150.11 170.66 1150.31 170.86 ;
      RECT 1149.71 170.66 1149.91 170.86 ;
      RECT 1149.31 170.66 1149.51 170.86 ;
      RECT 1148.91 170.66 1149.11 170.86 ;
      RECT 1111.24 170.66 1111.44 170.86 ;
      RECT 1110.84 170.66 1111.04 170.86 ;
      RECT 1110.44 170.66 1110.64 170.86 ;
      RECT 1110.04 170.66 1110.24 170.86 ;
      RECT 1072.37 170.66 1072.57 170.86 ;
      RECT 1071.97 170.66 1072.17 170.86 ;
      RECT 1071.57 170.66 1071.77 170.86 ;
      RECT 1071.17 170.66 1071.37 170.86 ;
      RECT 1033.5 170.66 1033.7 170.86 ;
      RECT 1033.1 170.66 1033.3 170.86 ;
      RECT 1032.7 170.66 1032.9 170.86 ;
      RECT 1032.3 170.66 1032.5 170.86 ;
      RECT 994.63 170.66 994.83 170.86 ;
      RECT 994.23 170.66 994.43 170.86 ;
      RECT 993.83 170.66 994.03 170.86 ;
      RECT 993.43 170.66 993.63 170.86 ;
      RECT 955.76 170.66 955.96 170.86 ;
      RECT 955.36 170.66 955.56 170.86 ;
      RECT 954.96 170.66 955.16 170.86 ;
      RECT 954.56 170.66 954.76 170.86 ;
      RECT 372.71 170.66 372.91 170.86 ;
      RECT 372.31 170.66 372.51 170.86 ;
      RECT 371.91 170.66 372.11 170.86 ;
      RECT 371.51 170.66 371.71 170.86 ;
      RECT 333.84 170.66 334.04 170.86 ;
      RECT 333.44 170.66 333.64 170.86 ;
      RECT 333.04 170.66 333.24 170.86 ;
      RECT 332.64 170.66 332.84 170.86 ;
      RECT 294.97 170.66 295.17 170.86 ;
      RECT 294.57 170.66 294.77 170.86 ;
      RECT 294.17 170.66 294.37 170.86 ;
      RECT 293.77 170.66 293.97 170.86 ;
      RECT 256.1 170.66 256.3 170.86 ;
      RECT 255.7 170.66 255.9 170.86 ;
      RECT 255.3 170.66 255.5 170.86 ;
      RECT 254.9 170.66 255.1 170.86 ;
      RECT 217.23 170.66 217.43 170.86 ;
      RECT 216.83 170.66 217.03 170.86 ;
      RECT 216.43 170.66 216.63 170.86 ;
      RECT 216.03 170.66 216.23 170.86 ;
      RECT 178.36 170.66 178.56 170.86 ;
      RECT 177.96 170.66 178.16 170.86 ;
      RECT 177.56 170.66 177.76 170.86 ;
      RECT 177.16 170.66 177.36 170.86 ;
      RECT 139.49 170.66 139.69 170.86 ;
      RECT 139.09 170.66 139.29 170.86 ;
      RECT 138.69 170.66 138.89 170.86 ;
      RECT 138.29 170.66 138.49 170.86 ;
      RECT 100.62 170.66 100.82 170.86 ;
      RECT 100.22 170.66 100.42 170.86 ;
      RECT 99.82 170.66 100.02 170.86 ;
      RECT 99.42 170.66 99.62 170.86 ;
      RECT 61.75 170.66 61.95 170.86 ;
      RECT 61.35 170.66 61.55 170.86 ;
      RECT 60.95 170.66 61.15 170.86 ;
      RECT 60.55 170.66 60.75 170.86 ;
      RECT 22.88 170.66 23.08 170.86 ;
      RECT 22.48 170.66 22.68 170.86 ;
      RECT 22.08 170.66 22.28 170.86 ;
      RECT 21.68 170.66 21.88 170.86 ;
      RECT 1344.46 170.26 1344.66 170.46 ;
      RECT 1344.06 170.26 1344.26 170.46 ;
      RECT 1343.66 170.26 1343.86 170.46 ;
      RECT 1343.26 170.26 1343.46 170.46 ;
      RECT 1305.59 170.26 1305.79 170.46 ;
      RECT 1305.19 170.26 1305.39 170.46 ;
      RECT 1304.79 170.26 1304.99 170.46 ;
      RECT 1304.39 170.26 1304.59 170.46 ;
      RECT 1266.72 170.26 1266.92 170.46 ;
      RECT 1266.32 170.26 1266.52 170.46 ;
      RECT 1265.92 170.26 1266.12 170.46 ;
      RECT 1265.52 170.26 1265.72 170.46 ;
      RECT 1227.85 170.26 1228.05 170.46 ;
      RECT 1227.45 170.26 1227.65 170.46 ;
      RECT 1227.05 170.26 1227.25 170.46 ;
      RECT 1226.65 170.26 1226.85 170.46 ;
      RECT 1188.98 170.26 1189.18 170.46 ;
      RECT 1188.58 170.26 1188.78 170.46 ;
      RECT 1188.18 170.26 1188.38 170.46 ;
      RECT 1187.78 170.26 1187.98 170.46 ;
      RECT 1150.11 170.26 1150.31 170.46 ;
      RECT 1149.71 170.26 1149.91 170.46 ;
      RECT 1149.31 170.26 1149.51 170.46 ;
      RECT 1148.91 170.26 1149.11 170.46 ;
      RECT 1111.24 170.26 1111.44 170.46 ;
      RECT 1110.84 170.26 1111.04 170.46 ;
      RECT 1110.44 170.26 1110.64 170.46 ;
      RECT 1110.04 170.26 1110.24 170.46 ;
      RECT 1072.37 170.26 1072.57 170.46 ;
      RECT 1071.97 170.26 1072.17 170.46 ;
      RECT 1071.57 170.26 1071.77 170.46 ;
      RECT 1071.17 170.26 1071.37 170.46 ;
      RECT 1033.5 170.26 1033.7 170.46 ;
      RECT 1033.1 170.26 1033.3 170.46 ;
      RECT 1032.7 170.26 1032.9 170.46 ;
      RECT 1032.3 170.26 1032.5 170.46 ;
      RECT 994.63 170.26 994.83 170.46 ;
      RECT 994.23 170.26 994.43 170.46 ;
      RECT 993.83 170.26 994.03 170.46 ;
      RECT 993.43 170.26 993.63 170.46 ;
      RECT 955.76 170.26 955.96 170.46 ;
      RECT 955.36 170.26 955.56 170.46 ;
      RECT 954.96 170.26 955.16 170.46 ;
      RECT 954.56 170.26 954.76 170.46 ;
      RECT 372.71 170.26 372.91 170.46 ;
      RECT 372.31 170.26 372.51 170.46 ;
      RECT 371.91 170.26 372.11 170.46 ;
      RECT 371.51 170.26 371.71 170.46 ;
      RECT 333.84 170.26 334.04 170.46 ;
      RECT 333.44 170.26 333.64 170.46 ;
      RECT 333.04 170.26 333.24 170.46 ;
      RECT 332.64 170.26 332.84 170.46 ;
      RECT 294.97 170.26 295.17 170.46 ;
      RECT 294.57 170.26 294.77 170.46 ;
      RECT 294.17 170.26 294.37 170.46 ;
      RECT 293.77 170.26 293.97 170.46 ;
      RECT 256.1 170.26 256.3 170.46 ;
      RECT 255.7 170.26 255.9 170.46 ;
      RECT 255.3 170.26 255.5 170.46 ;
      RECT 254.9 170.26 255.1 170.46 ;
      RECT 217.23 170.26 217.43 170.46 ;
      RECT 216.83 170.26 217.03 170.46 ;
      RECT 216.43 170.26 216.63 170.46 ;
      RECT 216.03 170.26 216.23 170.46 ;
      RECT 178.36 170.26 178.56 170.46 ;
      RECT 177.96 170.26 178.16 170.46 ;
      RECT 177.56 170.26 177.76 170.46 ;
      RECT 177.16 170.26 177.36 170.46 ;
      RECT 139.49 170.26 139.69 170.46 ;
      RECT 139.09 170.26 139.29 170.46 ;
      RECT 138.69 170.26 138.89 170.46 ;
      RECT 138.29 170.26 138.49 170.46 ;
      RECT 100.62 170.26 100.82 170.46 ;
      RECT 100.22 170.26 100.42 170.46 ;
      RECT 99.82 170.26 100.02 170.46 ;
      RECT 99.42 170.26 99.62 170.46 ;
      RECT 61.75 170.26 61.95 170.46 ;
      RECT 61.35 170.26 61.55 170.46 ;
      RECT 60.95 170.26 61.15 170.46 ;
      RECT 60.55 170.26 60.75 170.46 ;
      RECT 22.88 170.26 23.08 170.46 ;
      RECT 22.48 170.26 22.68 170.46 ;
      RECT 22.08 170.26 22.28 170.46 ;
      RECT 21.68 170.26 21.88 170.46 ;
      RECT 1344.46 169.86 1344.66 170.06 ;
      RECT 1344.06 169.86 1344.26 170.06 ;
      RECT 1343.66 169.86 1343.86 170.06 ;
      RECT 1343.26 169.86 1343.46 170.06 ;
      RECT 1305.59 169.86 1305.79 170.06 ;
      RECT 1305.19 169.86 1305.39 170.06 ;
      RECT 1304.79 169.86 1304.99 170.06 ;
      RECT 1304.39 169.86 1304.59 170.06 ;
      RECT 1266.72 169.86 1266.92 170.06 ;
      RECT 1266.32 169.86 1266.52 170.06 ;
      RECT 1265.92 169.86 1266.12 170.06 ;
      RECT 1265.52 169.86 1265.72 170.06 ;
      RECT 1227.85 169.86 1228.05 170.06 ;
      RECT 1227.45 169.86 1227.65 170.06 ;
      RECT 1227.05 169.86 1227.25 170.06 ;
      RECT 1226.65 169.86 1226.85 170.06 ;
      RECT 1188.98 169.86 1189.18 170.06 ;
      RECT 1188.58 169.86 1188.78 170.06 ;
      RECT 1188.18 169.86 1188.38 170.06 ;
      RECT 1187.78 169.86 1187.98 170.06 ;
      RECT 1150.11 169.86 1150.31 170.06 ;
      RECT 1149.71 169.86 1149.91 170.06 ;
      RECT 1149.31 169.86 1149.51 170.06 ;
      RECT 1148.91 169.86 1149.11 170.06 ;
      RECT 1111.24 169.86 1111.44 170.06 ;
      RECT 1110.84 169.86 1111.04 170.06 ;
      RECT 1110.44 169.86 1110.64 170.06 ;
      RECT 1110.04 169.86 1110.24 170.06 ;
      RECT 1072.37 169.86 1072.57 170.06 ;
      RECT 1071.97 169.86 1072.17 170.06 ;
      RECT 1071.57 169.86 1071.77 170.06 ;
      RECT 1071.17 169.86 1071.37 170.06 ;
      RECT 1033.5 169.86 1033.7 170.06 ;
      RECT 1033.1 169.86 1033.3 170.06 ;
      RECT 1032.7 169.86 1032.9 170.06 ;
      RECT 1032.3 169.86 1032.5 170.06 ;
      RECT 994.63 169.86 994.83 170.06 ;
      RECT 994.23 169.86 994.43 170.06 ;
      RECT 993.83 169.86 994.03 170.06 ;
      RECT 993.43 169.86 993.63 170.06 ;
      RECT 955.76 169.86 955.96 170.06 ;
      RECT 955.36 169.86 955.56 170.06 ;
      RECT 954.96 169.86 955.16 170.06 ;
      RECT 954.56 169.86 954.76 170.06 ;
      RECT 372.71 169.86 372.91 170.06 ;
      RECT 372.31 169.86 372.51 170.06 ;
      RECT 371.91 169.86 372.11 170.06 ;
      RECT 371.51 169.86 371.71 170.06 ;
      RECT 333.84 169.86 334.04 170.06 ;
      RECT 333.44 169.86 333.64 170.06 ;
      RECT 333.04 169.86 333.24 170.06 ;
      RECT 332.64 169.86 332.84 170.06 ;
      RECT 294.97 169.86 295.17 170.06 ;
      RECT 294.57 169.86 294.77 170.06 ;
      RECT 294.17 169.86 294.37 170.06 ;
      RECT 293.77 169.86 293.97 170.06 ;
      RECT 256.1 169.86 256.3 170.06 ;
      RECT 255.7 169.86 255.9 170.06 ;
      RECT 255.3 169.86 255.5 170.06 ;
      RECT 254.9 169.86 255.1 170.06 ;
      RECT 217.23 169.86 217.43 170.06 ;
      RECT 216.83 169.86 217.03 170.06 ;
      RECT 216.43 169.86 216.63 170.06 ;
      RECT 216.03 169.86 216.23 170.06 ;
      RECT 178.36 169.86 178.56 170.06 ;
      RECT 177.96 169.86 178.16 170.06 ;
      RECT 177.56 169.86 177.76 170.06 ;
      RECT 177.16 169.86 177.36 170.06 ;
      RECT 139.49 169.86 139.69 170.06 ;
      RECT 139.09 169.86 139.29 170.06 ;
      RECT 138.69 169.86 138.89 170.06 ;
      RECT 138.29 169.86 138.49 170.06 ;
      RECT 100.62 169.86 100.82 170.06 ;
      RECT 100.22 169.86 100.42 170.06 ;
      RECT 99.82 169.86 100.02 170.06 ;
      RECT 99.42 169.86 99.62 170.06 ;
      RECT 61.75 169.86 61.95 170.06 ;
      RECT 61.35 169.86 61.55 170.06 ;
      RECT 60.95 169.86 61.15 170.06 ;
      RECT 60.55 169.86 60.75 170.06 ;
      RECT 22.88 169.86 23.08 170.06 ;
      RECT 22.48 169.86 22.68 170.06 ;
      RECT 22.08 169.86 22.28 170.06 ;
      RECT 21.68 169.86 21.88 170.06 ;
      RECT 1344.46 169.46 1344.66 169.66 ;
      RECT 1344.06 169.46 1344.26 169.66 ;
      RECT 1343.66 169.46 1343.86 169.66 ;
      RECT 1343.26 169.46 1343.46 169.66 ;
      RECT 1305.59 169.46 1305.79 169.66 ;
      RECT 1305.19 169.46 1305.39 169.66 ;
      RECT 1304.79 169.46 1304.99 169.66 ;
      RECT 1304.39 169.46 1304.59 169.66 ;
      RECT 1266.72 169.46 1266.92 169.66 ;
      RECT 1266.32 169.46 1266.52 169.66 ;
      RECT 1265.92 169.46 1266.12 169.66 ;
      RECT 1265.52 169.46 1265.72 169.66 ;
      RECT 1227.85 169.46 1228.05 169.66 ;
      RECT 1227.45 169.46 1227.65 169.66 ;
      RECT 1227.05 169.46 1227.25 169.66 ;
      RECT 1226.65 169.46 1226.85 169.66 ;
      RECT 1188.98 169.46 1189.18 169.66 ;
      RECT 1188.58 169.46 1188.78 169.66 ;
      RECT 1188.18 169.46 1188.38 169.66 ;
      RECT 1187.78 169.46 1187.98 169.66 ;
      RECT 1150.11 169.46 1150.31 169.66 ;
      RECT 1149.71 169.46 1149.91 169.66 ;
      RECT 1149.31 169.46 1149.51 169.66 ;
      RECT 1148.91 169.46 1149.11 169.66 ;
      RECT 1111.24 169.46 1111.44 169.66 ;
      RECT 1110.84 169.46 1111.04 169.66 ;
      RECT 1110.44 169.46 1110.64 169.66 ;
      RECT 1110.04 169.46 1110.24 169.66 ;
      RECT 1072.37 169.46 1072.57 169.66 ;
      RECT 1071.97 169.46 1072.17 169.66 ;
      RECT 1071.57 169.46 1071.77 169.66 ;
      RECT 1071.17 169.46 1071.37 169.66 ;
      RECT 1033.5 169.46 1033.7 169.66 ;
      RECT 1033.1 169.46 1033.3 169.66 ;
      RECT 1032.7 169.46 1032.9 169.66 ;
      RECT 1032.3 169.46 1032.5 169.66 ;
      RECT 994.63 169.46 994.83 169.66 ;
      RECT 994.23 169.46 994.43 169.66 ;
      RECT 993.83 169.46 994.03 169.66 ;
      RECT 993.43 169.46 993.63 169.66 ;
      RECT 955.76 169.46 955.96 169.66 ;
      RECT 955.36 169.46 955.56 169.66 ;
      RECT 954.96 169.46 955.16 169.66 ;
      RECT 954.56 169.46 954.76 169.66 ;
      RECT 372.71 169.46 372.91 169.66 ;
      RECT 372.31 169.46 372.51 169.66 ;
      RECT 371.91 169.46 372.11 169.66 ;
      RECT 371.51 169.46 371.71 169.66 ;
      RECT 333.84 169.46 334.04 169.66 ;
      RECT 333.44 169.46 333.64 169.66 ;
      RECT 333.04 169.46 333.24 169.66 ;
      RECT 332.64 169.46 332.84 169.66 ;
      RECT 294.97 169.46 295.17 169.66 ;
      RECT 294.57 169.46 294.77 169.66 ;
      RECT 294.17 169.46 294.37 169.66 ;
      RECT 293.77 169.46 293.97 169.66 ;
      RECT 256.1 169.46 256.3 169.66 ;
      RECT 255.7 169.46 255.9 169.66 ;
      RECT 255.3 169.46 255.5 169.66 ;
      RECT 254.9 169.46 255.1 169.66 ;
      RECT 217.23 169.46 217.43 169.66 ;
      RECT 216.83 169.46 217.03 169.66 ;
      RECT 216.43 169.46 216.63 169.66 ;
      RECT 216.03 169.46 216.23 169.66 ;
      RECT 178.36 169.46 178.56 169.66 ;
      RECT 177.96 169.46 178.16 169.66 ;
      RECT 177.56 169.46 177.76 169.66 ;
      RECT 177.16 169.46 177.36 169.66 ;
      RECT 139.49 169.46 139.69 169.66 ;
      RECT 139.09 169.46 139.29 169.66 ;
      RECT 138.69 169.46 138.89 169.66 ;
      RECT 138.29 169.46 138.49 169.66 ;
      RECT 100.62 169.46 100.82 169.66 ;
      RECT 100.22 169.46 100.42 169.66 ;
      RECT 99.82 169.46 100.02 169.66 ;
      RECT 99.42 169.46 99.62 169.66 ;
      RECT 61.75 169.46 61.95 169.66 ;
      RECT 61.35 169.46 61.55 169.66 ;
      RECT 60.95 169.46 61.15 169.66 ;
      RECT 60.55 169.46 60.75 169.66 ;
      RECT 22.88 169.46 23.08 169.66 ;
      RECT 22.48 169.46 22.68 169.66 ;
      RECT 22.08 169.46 22.28 169.66 ;
      RECT 21.68 169.46 21.88 169.66 ;
      RECT 1341.16 159.1 1341.36 159.3 ;
      RECT 1340.76 159.1 1340.96 159.3 ;
      RECT 1340.36 159.1 1340.56 159.3 ;
      RECT 1339.96 159.1 1340.16 159.3 ;
      RECT 1302.29 159.1 1302.49 159.3 ;
      RECT 1301.89 159.1 1302.09 159.3 ;
      RECT 1301.49 159.1 1301.69 159.3 ;
      RECT 1301.09 159.1 1301.29 159.3 ;
      RECT 1263.42 159.1 1263.62 159.3 ;
      RECT 1263.02 159.1 1263.22 159.3 ;
      RECT 1262.62 159.1 1262.82 159.3 ;
      RECT 1262.22 159.1 1262.42 159.3 ;
      RECT 1224.55 159.1 1224.75 159.3 ;
      RECT 1224.15 159.1 1224.35 159.3 ;
      RECT 1223.75 159.1 1223.95 159.3 ;
      RECT 1223.35 159.1 1223.55 159.3 ;
      RECT 1185.68 159.1 1185.88 159.3 ;
      RECT 1185.28 159.1 1185.48 159.3 ;
      RECT 1184.88 159.1 1185.08 159.3 ;
      RECT 1184.48 159.1 1184.68 159.3 ;
      RECT 1146.81 159.1 1147.01 159.3 ;
      RECT 1146.41 159.1 1146.61 159.3 ;
      RECT 1146.01 159.1 1146.21 159.3 ;
      RECT 1145.61 159.1 1145.81 159.3 ;
      RECT 1107.94 159.1 1108.14 159.3 ;
      RECT 1107.54 159.1 1107.74 159.3 ;
      RECT 1107.14 159.1 1107.34 159.3 ;
      RECT 1106.74 159.1 1106.94 159.3 ;
      RECT 1069.07 159.1 1069.27 159.3 ;
      RECT 1068.67 159.1 1068.87 159.3 ;
      RECT 1068.27 159.1 1068.47 159.3 ;
      RECT 1067.87 159.1 1068.07 159.3 ;
      RECT 1030.2 159.1 1030.4 159.3 ;
      RECT 1029.8 159.1 1030 159.3 ;
      RECT 1029.4 159.1 1029.6 159.3 ;
      RECT 1029 159.1 1029.2 159.3 ;
      RECT 991.33 159.1 991.53 159.3 ;
      RECT 990.93 159.1 991.13 159.3 ;
      RECT 990.53 159.1 990.73 159.3 ;
      RECT 990.13 159.1 990.33 159.3 ;
      RECT 952.46 159.1 952.66 159.3 ;
      RECT 952.06 159.1 952.26 159.3 ;
      RECT 951.66 159.1 951.86 159.3 ;
      RECT 951.26 159.1 951.46 159.3 ;
      RECT 408.28 159.1 408.48 159.3 ;
      RECT 407.88 159.1 408.08 159.3 ;
      RECT 407.48 159.1 407.68 159.3 ;
      RECT 407.08 159.1 407.28 159.3 ;
      RECT 369.41 159.1 369.61 159.3 ;
      RECT 369.01 159.1 369.21 159.3 ;
      RECT 368.61 159.1 368.81 159.3 ;
      RECT 368.21 159.1 368.41 159.3 ;
      RECT 330.54 159.1 330.74 159.3 ;
      RECT 330.14 159.1 330.34 159.3 ;
      RECT 329.74 159.1 329.94 159.3 ;
      RECT 329.34 159.1 329.54 159.3 ;
      RECT 291.67 159.1 291.87 159.3 ;
      RECT 291.27 159.1 291.47 159.3 ;
      RECT 290.87 159.1 291.07 159.3 ;
      RECT 290.47 159.1 290.67 159.3 ;
      RECT 252.8 159.1 253 159.3 ;
      RECT 252.4 159.1 252.6 159.3 ;
      RECT 252 159.1 252.2 159.3 ;
      RECT 251.6 159.1 251.8 159.3 ;
      RECT 213.93 159.1 214.13 159.3 ;
      RECT 213.53 159.1 213.73 159.3 ;
      RECT 213.13 159.1 213.33 159.3 ;
      RECT 212.73 159.1 212.93 159.3 ;
      RECT 175.06 159.1 175.26 159.3 ;
      RECT 174.66 159.1 174.86 159.3 ;
      RECT 174.26 159.1 174.46 159.3 ;
      RECT 173.86 159.1 174.06 159.3 ;
      RECT 136.19 159.1 136.39 159.3 ;
      RECT 135.79 159.1 135.99 159.3 ;
      RECT 135.39 159.1 135.59 159.3 ;
      RECT 134.99 159.1 135.19 159.3 ;
      RECT 97.32 159.1 97.52 159.3 ;
      RECT 96.92 159.1 97.12 159.3 ;
      RECT 96.52 159.1 96.72 159.3 ;
      RECT 96.12 159.1 96.32 159.3 ;
      RECT 58.45 159.1 58.65 159.3 ;
      RECT 58.05 159.1 58.25 159.3 ;
      RECT 57.65 159.1 57.85 159.3 ;
      RECT 57.25 159.1 57.45 159.3 ;
      RECT 19.58 159.1 19.78 159.3 ;
      RECT 19.18 159.1 19.38 159.3 ;
      RECT 18.78 159.1 18.98 159.3 ;
      RECT 18.38 159.1 18.58 159.3 ;
      RECT 1341.16 158.7 1341.36 158.9 ;
      RECT 1340.76 158.7 1340.96 158.9 ;
      RECT 1340.36 158.7 1340.56 158.9 ;
      RECT 1339.96 158.7 1340.16 158.9 ;
      RECT 1302.29 158.7 1302.49 158.9 ;
      RECT 1301.89 158.7 1302.09 158.9 ;
      RECT 1301.49 158.7 1301.69 158.9 ;
      RECT 1301.09 158.7 1301.29 158.9 ;
      RECT 1263.42 158.7 1263.62 158.9 ;
      RECT 1263.02 158.7 1263.22 158.9 ;
      RECT 1262.62 158.7 1262.82 158.9 ;
      RECT 1262.22 158.7 1262.42 158.9 ;
      RECT 1224.55 158.7 1224.75 158.9 ;
      RECT 1224.15 158.7 1224.35 158.9 ;
      RECT 1223.75 158.7 1223.95 158.9 ;
      RECT 1223.35 158.7 1223.55 158.9 ;
      RECT 1185.68 158.7 1185.88 158.9 ;
      RECT 1185.28 158.7 1185.48 158.9 ;
      RECT 1184.88 158.7 1185.08 158.9 ;
      RECT 1184.48 158.7 1184.68 158.9 ;
      RECT 1146.81 158.7 1147.01 158.9 ;
      RECT 1146.41 158.7 1146.61 158.9 ;
      RECT 1146.01 158.7 1146.21 158.9 ;
      RECT 1145.61 158.7 1145.81 158.9 ;
      RECT 1107.94 158.7 1108.14 158.9 ;
      RECT 1107.54 158.7 1107.74 158.9 ;
      RECT 1107.14 158.7 1107.34 158.9 ;
      RECT 1106.74 158.7 1106.94 158.9 ;
      RECT 1069.07 158.7 1069.27 158.9 ;
      RECT 1068.67 158.7 1068.87 158.9 ;
      RECT 1068.27 158.7 1068.47 158.9 ;
      RECT 1067.87 158.7 1068.07 158.9 ;
      RECT 1030.2 158.7 1030.4 158.9 ;
      RECT 1029.8 158.7 1030 158.9 ;
      RECT 1029.4 158.7 1029.6 158.9 ;
      RECT 1029 158.7 1029.2 158.9 ;
      RECT 991.33 158.7 991.53 158.9 ;
      RECT 990.93 158.7 991.13 158.9 ;
      RECT 990.53 158.7 990.73 158.9 ;
      RECT 990.13 158.7 990.33 158.9 ;
      RECT 952.46 158.7 952.66 158.9 ;
      RECT 952.06 158.7 952.26 158.9 ;
      RECT 951.66 158.7 951.86 158.9 ;
      RECT 951.26 158.7 951.46 158.9 ;
      RECT 408.28 158.7 408.48 158.9 ;
      RECT 407.88 158.7 408.08 158.9 ;
      RECT 407.48 158.7 407.68 158.9 ;
      RECT 407.08 158.7 407.28 158.9 ;
      RECT 369.41 158.7 369.61 158.9 ;
      RECT 369.01 158.7 369.21 158.9 ;
      RECT 368.61 158.7 368.81 158.9 ;
      RECT 368.21 158.7 368.41 158.9 ;
      RECT 330.54 158.7 330.74 158.9 ;
      RECT 330.14 158.7 330.34 158.9 ;
      RECT 329.74 158.7 329.94 158.9 ;
      RECT 329.34 158.7 329.54 158.9 ;
      RECT 291.67 158.7 291.87 158.9 ;
      RECT 291.27 158.7 291.47 158.9 ;
      RECT 290.87 158.7 291.07 158.9 ;
      RECT 290.47 158.7 290.67 158.9 ;
      RECT 252.8 158.7 253 158.9 ;
      RECT 252.4 158.7 252.6 158.9 ;
      RECT 252 158.7 252.2 158.9 ;
      RECT 251.6 158.7 251.8 158.9 ;
      RECT 213.93 158.7 214.13 158.9 ;
      RECT 213.53 158.7 213.73 158.9 ;
      RECT 213.13 158.7 213.33 158.9 ;
      RECT 212.73 158.7 212.93 158.9 ;
      RECT 175.06 158.7 175.26 158.9 ;
      RECT 174.66 158.7 174.86 158.9 ;
      RECT 174.26 158.7 174.46 158.9 ;
      RECT 173.86 158.7 174.06 158.9 ;
      RECT 136.19 158.7 136.39 158.9 ;
      RECT 135.79 158.7 135.99 158.9 ;
      RECT 135.39 158.7 135.59 158.9 ;
      RECT 134.99 158.7 135.19 158.9 ;
      RECT 97.32 158.7 97.52 158.9 ;
      RECT 96.92 158.7 97.12 158.9 ;
      RECT 96.52 158.7 96.72 158.9 ;
      RECT 96.12 158.7 96.32 158.9 ;
      RECT 58.45 158.7 58.65 158.9 ;
      RECT 58.05 158.7 58.25 158.9 ;
      RECT 57.65 158.7 57.85 158.9 ;
      RECT 57.25 158.7 57.45 158.9 ;
      RECT 19.58 158.7 19.78 158.9 ;
      RECT 19.18 158.7 19.38 158.9 ;
      RECT 18.78 158.7 18.98 158.9 ;
      RECT 18.38 158.7 18.58 158.9 ;
      RECT 1341.16 158.3 1341.36 158.5 ;
      RECT 1340.76 158.3 1340.96 158.5 ;
      RECT 1340.36 158.3 1340.56 158.5 ;
      RECT 1339.96 158.3 1340.16 158.5 ;
      RECT 1302.29 158.3 1302.49 158.5 ;
      RECT 1301.89 158.3 1302.09 158.5 ;
      RECT 1301.49 158.3 1301.69 158.5 ;
      RECT 1301.09 158.3 1301.29 158.5 ;
      RECT 1263.42 158.3 1263.62 158.5 ;
      RECT 1263.02 158.3 1263.22 158.5 ;
      RECT 1262.62 158.3 1262.82 158.5 ;
      RECT 1262.22 158.3 1262.42 158.5 ;
      RECT 1224.55 158.3 1224.75 158.5 ;
      RECT 1224.15 158.3 1224.35 158.5 ;
      RECT 1223.75 158.3 1223.95 158.5 ;
      RECT 1223.35 158.3 1223.55 158.5 ;
      RECT 1185.68 158.3 1185.88 158.5 ;
      RECT 1185.28 158.3 1185.48 158.5 ;
      RECT 1184.88 158.3 1185.08 158.5 ;
      RECT 1184.48 158.3 1184.68 158.5 ;
      RECT 1146.81 158.3 1147.01 158.5 ;
      RECT 1146.41 158.3 1146.61 158.5 ;
      RECT 1146.01 158.3 1146.21 158.5 ;
      RECT 1145.61 158.3 1145.81 158.5 ;
      RECT 1107.94 158.3 1108.14 158.5 ;
      RECT 1107.54 158.3 1107.74 158.5 ;
      RECT 1107.14 158.3 1107.34 158.5 ;
      RECT 1106.74 158.3 1106.94 158.5 ;
      RECT 1069.07 158.3 1069.27 158.5 ;
      RECT 1068.67 158.3 1068.87 158.5 ;
      RECT 1068.27 158.3 1068.47 158.5 ;
      RECT 1067.87 158.3 1068.07 158.5 ;
      RECT 1030.2 158.3 1030.4 158.5 ;
      RECT 1029.8 158.3 1030 158.5 ;
      RECT 1029.4 158.3 1029.6 158.5 ;
      RECT 1029 158.3 1029.2 158.5 ;
      RECT 991.33 158.3 991.53 158.5 ;
      RECT 990.93 158.3 991.13 158.5 ;
      RECT 990.53 158.3 990.73 158.5 ;
      RECT 990.13 158.3 990.33 158.5 ;
      RECT 952.46 158.3 952.66 158.5 ;
      RECT 952.06 158.3 952.26 158.5 ;
      RECT 951.66 158.3 951.86 158.5 ;
      RECT 951.26 158.3 951.46 158.5 ;
      RECT 408.28 158.3 408.48 158.5 ;
      RECT 407.88 158.3 408.08 158.5 ;
      RECT 407.48 158.3 407.68 158.5 ;
      RECT 407.08 158.3 407.28 158.5 ;
      RECT 369.41 158.3 369.61 158.5 ;
      RECT 369.01 158.3 369.21 158.5 ;
      RECT 368.61 158.3 368.81 158.5 ;
      RECT 368.21 158.3 368.41 158.5 ;
      RECT 330.54 158.3 330.74 158.5 ;
      RECT 330.14 158.3 330.34 158.5 ;
      RECT 329.74 158.3 329.94 158.5 ;
      RECT 329.34 158.3 329.54 158.5 ;
      RECT 291.67 158.3 291.87 158.5 ;
      RECT 291.27 158.3 291.47 158.5 ;
      RECT 290.87 158.3 291.07 158.5 ;
      RECT 290.47 158.3 290.67 158.5 ;
      RECT 252.8 158.3 253 158.5 ;
      RECT 252.4 158.3 252.6 158.5 ;
      RECT 252 158.3 252.2 158.5 ;
      RECT 251.6 158.3 251.8 158.5 ;
      RECT 213.93 158.3 214.13 158.5 ;
      RECT 213.53 158.3 213.73 158.5 ;
      RECT 213.13 158.3 213.33 158.5 ;
      RECT 212.73 158.3 212.93 158.5 ;
      RECT 175.06 158.3 175.26 158.5 ;
      RECT 174.66 158.3 174.86 158.5 ;
      RECT 174.26 158.3 174.46 158.5 ;
      RECT 173.86 158.3 174.06 158.5 ;
      RECT 136.19 158.3 136.39 158.5 ;
      RECT 135.79 158.3 135.99 158.5 ;
      RECT 135.39 158.3 135.59 158.5 ;
      RECT 134.99 158.3 135.19 158.5 ;
      RECT 97.32 158.3 97.52 158.5 ;
      RECT 96.92 158.3 97.12 158.5 ;
      RECT 96.52 158.3 96.72 158.5 ;
      RECT 96.12 158.3 96.32 158.5 ;
      RECT 58.45 158.3 58.65 158.5 ;
      RECT 58.05 158.3 58.25 158.5 ;
      RECT 57.65 158.3 57.85 158.5 ;
      RECT 57.25 158.3 57.45 158.5 ;
      RECT 19.58 158.3 19.78 158.5 ;
      RECT 19.18 158.3 19.38 158.5 ;
      RECT 18.78 158.3 18.98 158.5 ;
      RECT 18.38 158.3 18.58 158.5 ;
      RECT 1341.16 157.9 1341.36 158.1 ;
      RECT 1340.76 157.9 1340.96 158.1 ;
      RECT 1340.36 157.9 1340.56 158.1 ;
      RECT 1339.96 157.9 1340.16 158.1 ;
      RECT 1302.29 157.9 1302.49 158.1 ;
      RECT 1301.89 157.9 1302.09 158.1 ;
      RECT 1301.49 157.9 1301.69 158.1 ;
      RECT 1301.09 157.9 1301.29 158.1 ;
      RECT 1263.42 157.9 1263.62 158.1 ;
      RECT 1263.02 157.9 1263.22 158.1 ;
      RECT 1262.62 157.9 1262.82 158.1 ;
      RECT 1262.22 157.9 1262.42 158.1 ;
      RECT 1224.55 157.9 1224.75 158.1 ;
      RECT 1224.15 157.9 1224.35 158.1 ;
      RECT 1223.75 157.9 1223.95 158.1 ;
      RECT 1223.35 157.9 1223.55 158.1 ;
      RECT 1185.68 157.9 1185.88 158.1 ;
      RECT 1185.28 157.9 1185.48 158.1 ;
      RECT 1184.88 157.9 1185.08 158.1 ;
      RECT 1184.48 157.9 1184.68 158.1 ;
      RECT 1146.81 157.9 1147.01 158.1 ;
      RECT 1146.41 157.9 1146.61 158.1 ;
      RECT 1146.01 157.9 1146.21 158.1 ;
      RECT 1145.61 157.9 1145.81 158.1 ;
      RECT 1107.94 157.9 1108.14 158.1 ;
      RECT 1107.54 157.9 1107.74 158.1 ;
      RECT 1107.14 157.9 1107.34 158.1 ;
      RECT 1106.74 157.9 1106.94 158.1 ;
      RECT 1069.07 157.9 1069.27 158.1 ;
      RECT 1068.67 157.9 1068.87 158.1 ;
      RECT 1068.27 157.9 1068.47 158.1 ;
      RECT 1067.87 157.9 1068.07 158.1 ;
      RECT 1030.2 157.9 1030.4 158.1 ;
      RECT 1029.8 157.9 1030 158.1 ;
      RECT 1029.4 157.9 1029.6 158.1 ;
      RECT 1029 157.9 1029.2 158.1 ;
      RECT 991.33 157.9 991.53 158.1 ;
      RECT 990.93 157.9 991.13 158.1 ;
      RECT 990.53 157.9 990.73 158.1 ;
      RECT 990.13 157.9 990.33 158.1 ;
      RECT 952.46 157.9 952.66 158.1 ;
      RECT 952.06 157.9 952.26 158.1 ;
      RECT 951.66 157.9 951.86 158.1 ;
      RECT 951.26 157.9 951.46 158.1 ;
      RECT 408.28 157.9 408.48 158.1 ;
      RECT 407.88 157.9 408.08 158.1 ;
      RECT 407.48 157.9 407.68 158.1 ;
      RECT 407.08 157.9 407.28 158.1 ;
      RECT 369.41 157.9 369.61 158.1 ;
      RECT 369.01 157.9 369.21 158.1 ;
      RECT 368.61 157.9 368.81 158.1 ;
      RECT 368.21 157.9 368.41 158.1 ;
      RECT 330.54 157.9 330.74 158.1 ;
      RECT 330.14 157.9 330.34 158.1 ;
      RECT 329.74 157.9 329.94 158.1 ;
      RECT 329.34 157.9 329.54 158.1 ;
      RECT 291.67 157.9 291.87 158.1 ;
      RECT 291.27 157.9 291.47 158.1 ;
      RECT 290.87 157.9 291.07 158.1 ;
      RECT 290.47 157.9 290.67 158.1 ;
      RECT 252.8 157.9 253 158.1 ;
      RECT 252.4 157.9 252.6 158.1 ;
      RECT 252 157.9 252.2 158.1 ;
      RECT 251.6 157.9 251.8 158.1 ;
      RECT 213.93 157.9 214.13 158.1 ;
      RECT 213.53 157.9 213.73 158.1 ;
      RECT 213.13 157.9 213.33 158.1 ;
      RECT 212.73 157.9 212.93 158.1 ;
      RECT 175.06 157.9 175.26 158.1 ;
      RECT 174.66 157.9 174.86 158.1 ;
      RECT 174.26 157.9 174.46 158.1 ;
      RECT 173.86 157.9 174.06 158.1 ;
      RECT 136.19 157.9 136.39 158.1 ;
      RECT 135.79 157.9 135.99 158.1 ;
      RECT 135.39 157.9 135.59 158.1 ;
      RECT 134.99 157.9 135.19 158.1 ;
      RECT 97.32 157.9 97.52 158.1 ;
      RECT 96.92 157.9 97.12 158.1 ;
      RECT 96.52 157.9 96.72 158.1 ;
      RECT 96.12 157.9 96.32 158.1 ;
      RECT 58.45 157.9 58.65 158.1 ;
      RECT 58.05 157.9 58.25 158.1 ;
      RECT 57.65 157.9 57.85 158.1 ;
      RECT 57.25 157.9 57.45 158.1 ;
      RECT 19.58 157.9 19.78 158.1 ;
      RECT 19.18 157.9 19.38 158.1 ;
      RECT 18.78 157.9 18.98 158.1 ;
      RECT 18.38 157.9 18.58 158.1 ;
      RECT 1150.78 142.06 1150.98 142.26 ;
      RECT 1150.78 136.62 1150.98 136.82 ;
      RECT 995.3 136.62 995.5 136.82 ;
      RECT 1150.78 115.54 1150.98 115.74 ;
      RECT 1150.78 98.54 1150.98 98.74 ;
      RECT 1150.78 88.34 1150.98 88.54 ;
      RECT 1344.46 80.9 1344.66 81.1 ;
      RECT 1344.06 80.9 1344.26 81.1 ;
      RECT 1343.66 80.9 1343.86 81.1 ;
      RECT 1343.26 80.9 1343.46 81.1 ;
      RECT 1305.59 80.9 1305.79 81.1 ;
      RECT 1305.19 80.9 1305.39 81.1 ;
      RECT 1304.79 80.9 1304.99 81.1 ;
      RECT 1304.39 80.9 1304.59 81.1 ;
      RECT 1266.72 80.9 1266.92 81.1 ;
      RECT 1266.32 80.9 1266.52 81.1 ;
      RECT 1265.92 80.9 1266.12 81.1 ;
      RECT 1265.52 80.9 1265.72 81.1 ;
      RECT 1227.85 80.9 1228.05 81.1 ;
      RECT 1227.45 80.9 1227.65 81.1 ;
      RECT 1227.05 80.9 1227.25 81.1 ;
      RECT 1226.65 80.9 1226.85 81.1 ;
      RECT 1188.98 80.9 1189.18 81.1 ;
      RECT 1188.58 80.9 1188.78 81.1 ;
      RECT 1188.18 80.9 1188.38 81.1 ;
      RECT 1187.78 80.9 1187.98 81.1 ;
      RECT 1150.11 80.9 1150.31 81.1 ;
      RECT 1149.71 80.9 1149.91 81.1 ;
      RECT 1149.31 80.9 1149.51 81.1 ;
      RECT 1148.91 80.9 1149.11 81.1 ;
      RECT 1111.24 80.9 1111.44 81.1 ;
      RECT 1110.84 80.9 1111.04 81.1 ;
      RECT 1110.44 80.9 1110.64 81.1 ;
      RECT 1110.04 80.9 1110.24 81.1 ;
      RECT 1072.37 80.9 1072.57 81.1 ;
      RECT 1071.97 80.9 1072.17 81.1 ;
      RECT 1071.57 80.9 1071.77 81.1 ;
      RECT 1071.17 80.9 1071.37 81.1 ;
      RECT 1033.5 80.9 1033.7 81.1 ;
      RECT 1033.1 80.9 1033.3 81.1 ;
      RECT 1032.7 80.9 1032.9 81.1 ;
      RECT 1032.3 80.9 1032.5 81.1 ;
      RECT 994.63 80.9 994.83 81.1 ;
      RECT 994.23 80.9 994.43 81.1 ;
      RECT 993.83 80.9 994.03 81.1 ;
      RECT 993.43 80.9 993.63 81.1 ;
      RECT 955.76 80.9 955.96 81.1 ;
      RECT 955.36 80.9 955.56 81.1 ;
      RECT 954.96 80.9 955.16 81.1 ;
      RECT 954.56 80.9 954.76 81.1 ;
      RECT 372.71 80.9 372.91 81.1 ;
      RECT 372.31 80.9 372.51 81.1 ;
      RECT 371.91 80.9 372.11 81.1 ;
      RECT 371.51 80.9 371.71 81.1 ;
      RECT 333.84 80.9 334.04 81.1 ;
      RECT 333.44 80.9 333.64 81.1 ;
      RECT 333.04 80.9 333.24 81.1 ;
      RECT 332.64 80.9 332.84 81.1 ;
      RECT 294.97 80.9 295.17 81.1 ;
      RECT 294.57 80.9 294.77 81.1 ;
      RECT 294.17 80.9 294.37 81.1 ;
      RECT 293.77 80.9 293.97 81.1 ;
      RECT 256.1 80.9 256.3 81.1 ;
      RECT 255.7 80.9 255.9 81.1 ;
      RECT 255.3 80.9 255.5 81.1 ;
      RECT 254.9 80.9 255.1 81.1 ;
      RECT 217.23 80.9 217.43 81.1 ;
      RECT 216.83 80.9 217.03 81.1 ;
      RECT 216.43 80.9 216.63 81.1 ;
      RECT 216.03 80.9 216.23 81.1 ;
      RECT 178.36 80.9 178.56 81.1 ;
      RECT 177.96 80.9 178.16 81.1 ;
      RECT 177.56 80.9 177.76 81.1 ;
      RECT 177.16 80.9 177.36 81.1 ;
      RECT 139.49 80.9 139.69 81.1 ;
      RECT 139.09 80.9 139.29 81.1 ;
      RECT 138.69 80.9 138.89 81.1 ;
      RECT 138.29 80.9 138.49 81.1 ;
      RECT 100.62 80.9 100.82 81.1 ;
      RECT 100.22 80.9 100.42 81.1 ;
      RECT 99.82 80.9 100.02 81.1 ;
      RECT 99.42 80.9 99.62 81.1 ;
      RECT 61.75 80.9 61.95 81.1 ;
      RECT 61.35 80.9 61.55 81.1 ;
      RECT 60.95 80.9 61.15 81.1 ;
      RECT 60.55 80.9 60.75 81.1 ;
      RECT 22.88 80.9 23.08 81.1 ;
      RECT 22.48 80.9 22.68 81.1 ;
      RECT 22.08 80.9 22.28 81.1 ;
      RECT 21.68 80.9 21.88 81.1 ;
      RECT 1344.46 80.5 1344.66 80.7 ;
      RECT 1344.06 80.5 1344.26 80.7 ;
      RECT 1343.66 80.5 1343.86 80.7 ;
      RECT 1343.26 80.5 1343.46 80.7 ;
      RECT 1305.59 80.5 1305.79 80.7 ;
      RECT 1305.19 80.5 1305.39 80.7 ;
      RECT 1304.79 80.5 1304.99 80.7 ;
      RECT 1304.39 80.5 1304.59 80.7 ;
      RECT 1266.72 80.5 1266.92 80.7 ;
      RECT 1266.32 80.5 1266.52 80.7 ;
      RECT 1265.92 80.5 1266.12 80.7 ;
      RECT 1265.52 80.5 1265.72 80.7 ;
      RECT 1227.85 80.5 1228.05 80.7 ;
      RECT 1227.45 80.5 1227.65 80.7 ;
      RECT 1227.05 80.5 1227.25 80.7 ;
      RECT 1226.65 80.5 1226.85 80.7 ;
      RECT 1188.98 80.5 1189.18 80.7 ;
      RECT 1188.58 80.5 1188.78 80.7 ;
      RECT 1188.18 80.5 1188.38 80.7 ;
      RECT 1187.78 80.5 1187.98 80.7 ;
      RECT 1150.11 80.5 1150.31 80.7 ;
      RECT 1149.71 80.5 1149.91 80.7 ;
      RECT 1149.31 80.5 1149.51 80.7 ;
      RECT 1148.91 80.5 1149.11 80.7 ;
      RECT 1111.24 80.5 1111.44 80.7 ;
      RECT 1110.84 80.5 1111.04 80.7 ;
      RECT 1110.44 80.5 1110.64 80.7 ;
      RECT 1110.04 80.5 1110.24 80.7 ;
      RECT 1072.37 80.5 1072.57 80.7 ;
      RECT 1071.97 80.5 1072.17 80.7 ;
      RECT 1071.57 80.5 1071.77 80.7 ;
      RECT 1071.17 80.5 1071.37 80.7 ;
      RECT 1033.5 80.5 1033.7 80.7 ;
      RECT 1033.1 80.5 1033.3 80.7 ;
      RECT 1032.7 80.5 1032.9 80.7 ;
      RECT 1032.3 80.5 1032.5 80.7 ;
      RECT 994.63 80.5 994.83 80.7 ;
      RECT 994.23 80.5 994.43 80.7 ;
      RECT 993.83 80.5 994.03 80.7 ;
      RECT 993.43 80.5 993.63 80.7 ;
      RECT 955.76 80.5 955.96 80.7 ;
      RECT 955.36 80.5 955.56 80.7 ;
      RECT 954.96 80.5 955.16 80.7 ;
      RECT 954.56 80.5 954.76 80.7 ;
      RECT 372.71 80.5 372.91 80.7 ;
      RECT 372.31 80.5 372.51 80.7 ;
      RECT 371.91 80.5 372.11 80.7 ;
      RECT 371.51 80.5 371.71 80.7 ;
      RECT 333.84 80.5 334.04 80.7 ;
      RECT 333.44 80.5 333.64 80.7 ;
      RECT 333.04 80.5 333.24 80.7 ;
      RECT 332.64 80.5 332.84 80.7 ;
      RECT 294.97 80.5 295.17 80.7 ;
      RECT 294.57 80.5 294.77 80.7 ;
      RECT 294.17 80.5 294.37 80.7 ;
      RECT 293.77 80.5 293.97 80.7 ;
      RECT 256.1 80.5 256.3 80.7 ;
      RECT 255.7 80.5 255.9 80.7 ;
      RECT 255.3 80.5 255.5 80.7 ;
      RECT 254.9 80.5 255.1 80.7 ;
      RECT 217.23 80.5 217.43 80.7 ;
      RECT 216.83 80.5 217.03 80.7 ;
      RECT 216.43 80.5 216.63 80.7 ;
      RECT 216.03 80.5 216.23 80.7 ;
      RECT 178.36 80.5 178.56 80.7 ;
      RECT 177.96 80.5 178.16 80.7 ;
      RECT 177.56 80.5 177.76 80.7 ;
      RECT 177.16 80.5 177.36 80.7 ;
      RECT 139.49 80.5 139.69 80.7 ;
      RECT 139.09 80.5 139.29 80.7 ;
      RECT 138.69 80.5 138.89 80.7 ;
      RECT 138.29 80.5 138.49 80.7 ;
      RECT 100.62 80.5 100.82 80.7 ;
      RECT 100.22 80.5 100.42 80.7 ;
      RECT 99.82 80.5 100.02 80.7 ;
      RECT 99.42 80.5 99.62 80.7 ;
      RECT 61.75 80.5 61.95 80.7 ;
      RECT 61.35 80.5 61.55 80.7 ;
      RECT 60.95 80.5 61.15 80.7 ;
      RECT 60.55 80.5 60.75 80.7 ;
      RECT 22.88 80.5 23.08 80.7 ;
      RECT 22.48 80.5 22.68 80.7 ;
      RECT 22.08 80.5 22.28 80.7 ;
      RECT 21.68 80.5 21.88 80.7 ;
      RECT 1344.46 80.1 1344.66 80.3 ;
      RECT 1344.06 80.1 1344.26 80.3 ;
      RECT 1343.66 80.1 1343.86 80.3 ;
      RECT 1343.26 80.1 1343.46 80.3 ;
      RECT 1305.59 80.1 1305.79 80.3 ;
      RECT 1305.19 80.1 1305.39 80.3 ;
      RECT 1304.79 80.1 1304.99 80.3 ;
      RECT 1304.39 80.1 1304.59 80.3 ;
      RECT 1266.72 80.1 1266.92 80.3 ;
      RECT 1266.32 80.1 1266.52 80.3 ;
      RECT 1265.92 80.1 1266.12 80.3 ;
      RECT 1265.52 80.1 1265.72 80.3 ;
      RECT 1227.85 80.1 1228.05 80.3 ;
      RECT 1227.45 80.1 1227.65 80.3 ;
      RECT 1227.05 80.1 1227.25 80.3 ;
      RECT 1226.65 80.1 1226.85 80.3 ;
      RECT 1188.98 80.1 1189.18 80.3 ;
      RECT 1188.58 80.1 1188.78 80.3 ;
      RECT 1188.18 80.1 1188.38 80.3 ;
      RECT 1187.78 80.1 1187.98 80.3 ;
      RECT 1150.11 80.1 1150.31 80.3 ;
      RECT 1149.71 80.1 1149.91 80.3 ;
      RECT 1149.31 80.1 1149.51 80.3 ;
      RECT 1148.91 80.1 1149.11 80.3 ;
      RECT 1111.24 80.1 1111.44 80.3 ;
      RECT 1110.84 80.1 1111.04 80.3 ;
      RECT 1110.44 80.1 1110.64 80.3 ;
      RECT 1110.04 80.1 1110.24 80.3 ;
      RECT 1072.37 80.1 1072.57 80.3 ;
      RECT 1071.97 80.1 1072.17 80.3 ;
      RECT 1071.57 80.1 1071.77 80.3 ;
      RECT 1071.17 80.1 1071.37 80.3 ;
      RECT 1033.5 80.1 1033.7 80.3 ;
      RECT 1033.1 80.1 1033.3 80.3 ;
      RECT 1032.7 80.1 1032.9 80.3 ;
      RECT 1032.3 80.1 1032.5 80.3 ;
      RECT 994.63 80.1 994.83 80.3 ;
      RECT 994.23 80.1 994.43 80.3 ;
      RECT 993.83 80.1 994.03 80.3 ;
      RECT 993.43 80.1 993.63 80.3 ;
      RECT 955.76 80.1 955.96 80.3 ;
      RECT 955.36 80.1 955.56 80.3 ;
      RECT 954.96 80.1 955.16 80.3 ;
      RECT 954.56 80.1 954.76 80.3 ;
      RECT 372.71 80.1 372.91 80.3 ;
      RECT 372.31 80.1 372.51 80.3 ;
      RECT 371.91 80.1 372.11 80.3 ;
      RECT 371.51 80.1 371.71 80.3 ;
      RECT 333.84 80.1 334.04 80.3 ;
      RECT 333.44 80.1 333.64 80.3 ;
      RECT 333.04 80.1 333.24 80.3 ;
      RECT 332.64 80.1 332.84 80.3 ;
      RECT 294.97 80.1 295.17 80.3 ;
      RECT 294.57 80.1 294.77 80.3 ;
      RECT 294.17 80.1 294.37 80.3 ;
      RECT 293.77 80.1 293.97 80.3 ;
      RECT 256.1 80.1 256.3 80.3 ;
      RECT 255.7 80.1 255.9 80.3 ;
      RECT 255.3 80.1 255.5 80.3 ;
      RECT 254.9 80.1 255.1 80.3 ;
      RECT 217.23 80.1 217.43 80.3 ;
      RECT 216.83 80.1 217.03 80.3 ;
      RECT 216.43 80.1 216.63 80.3 ;
      RECT 216.03 80.1 216.23 80.3 ;
      RECT 178.36 80.1 178.56 80.3 ;
      RECT 177.96 80.1 178.16 80.3 ;
      RECT 177.56 80.1 177.76 80.3 ;
      RECT 177.16 80.1 177.36 80.3 ;
      RECT 139.49 80.1 139.69 80.3 ;
      RECT 139.09 80.1 139.29 80.3 ;
      RECT 138.69 80.1 138.89 80.3 ;
      RECT 138.29 80.1 138.49 80.3 ;
      RECT 100.62 80.1 100.82 80.3 ;
      RECT 100.22 80.1 100.42 80.3 ;
      RECT 99.82 80.1 100.02 80.3 ;
      RECT 99.42 80.1 99.62 80.3 ;
      RECT 61.75 80.1 61.95 80.3 ;
      RECT 61.35 80.1 61.55 80.3 ;
      RECT 60.95 80.1 61.15 80.3 ;
      RECT 60.55 80.1 60.75 80.3 ;
      RECT 22.88 80.1 23.08 80.3 ;
      RECT 22.48 80.1 22.68 80.3 ;
      RECT 22.08 80.1 22.28 80.3 ;
      RECT 21.68 80.1 21.88 80.3 ;
      RECT 1344.46 79.7 1344.66 79.9 ;
      RECT 1344.06 79.7 1344.26 79.9 ;
      RECT 1343.66 79.7 1343.86 79.9 ;
      RECT 1343.26 79.7 1343.46 79.9 ;
      RECT 1305.59 79.7 1305.79 79.9 ;
      RECT 1305.19 79.7 1305.39 79.9 ;
      RECT 1304.79 79.7 1304.99 79.9 ;
      RECT 1304.39 79.7 1304.59 79.9 ;
      RECT 1266.72 79.7 1266.92 79.9 ;
      RECT 1266.32 79.7 1266.52 79.9 ;
      RECT 1265.92 79.7 1266.12 79.9 ;
      RECT 1265.52 79.7 1265.72 79.9 ;
      RECT 1227.85 79.7 1228.05 79.9 ;
      RECT 1227.45 79.7 1227.65 79.9 ;
      RECT 1227.05 79.7 1227.25 79.9 ;
      RECT 1226.65 79.7 1226.85 79.9 ;
      RECT 1188.98 79.7 1189.18 79.9 ;
      RECT 1188.58 79.7 1188.78 79.9 ;
      RECT 1188.18 79.7 1188.38 79.9 ;
      RECT 1187.78 79.7 1187.98 79.9 ;
      RECT 1150.11 79.7 1150.31 79.9 ;
      RECT 1149.71 79.7 1149.91 79.9 ;
      RECT 1149.31 79.7 1149.51 79.9 ;
      RECT 1148.91 79.7 1149.11 79.9 ;
      RECT 1111.24 79.7 1111.44 79.9 ;
      RECT 1110.84 79.7 1111.04 79.9 ;
      RECT 1110.44 79.7 1110.64 79.9 ;
      RECT 1110.04 79.7 1110.24 79.9 ;
      RECT 1072.37 79.7 1072.57 79.9 ;
      RECT 1071.97 79.7 1072.17 79.9 ;
      RECT 1071.57 79.7 1071.77 79.9 ;
      RECT 1071.17 79.7 1071.37 79.9 ;
      RECT 1033.5 79.7 1033.7 79.9 ;
      RECT 1033.1 79.7 1033.3 79.9 ;
      RECT 1032.7 79.7 1032.9 79.9 ;
      RECT 1032.3 79.7 1032.5 79.9 ;
      RECT 994.63 79.7 994.83 79.9 ;
      RECT 994.23 79.7 994.43 79.9 ;
      RECT 993.83 79.7 994.03 79.9 ;
      RECT 993.43 79.7 993.63 79.9 ;
      RECT 955.76 79.7 955.96 79.9 ;
      RECT 955.36 79.7 955.56 79.9 ;
      RECT 954.96 79.7 955.16 79.9 ;
      RECT 954.56 79.7 954.76 79.9 ;
      RECT 372.71 79.7 372.91 79.9 ;
      RECT 372.31 79.7 372.51 79.9 ;
      RECT 371.91 79.7 372.11 79.9 ;
      RECT 371.51 79.7 371.71 79.9 ;
      RECT 333.84 79.7 334.04 79.9 ;
      RECT 333.44 79.7 333.64 79.9 ;
      RECT 333.04 79.7 333.24 79.9 ;
      RECT 332.64 79.7 332.84 79.9 ;
      RECT 294.97 79.7 295.17 79.9 ;
      RECT 294.57 79.7 294.77 79.9 ;
      RECT 294.17 79.7 294.37 79.9 ;
      RECT 293.77 79.7 293.97 79.9 ;
      RECT 256.1 79.7 256.3 79.9 ;
      RECT 255.7 79.7 255.9 79.9 ;
      RECT 255.3 79.7 255.5 79.9 ;
      RECT 254.9 79.7 255.1 79.9 ;
      RECT 217.23 79.7 217.43 79.9 ;
      RECT 216.83 79.7 217.03 79.9 ;
      RECT 216.43 79.7 216.63 79.9 ;
      RECT 216.03 79.7 216.23 79.9 ;
      RECT 178.36 79.7 178.56 79.9 ;
      RECT 177.96 79.7 178.16 79.9 ;
      RECT 177.56 79.7 177.76 79.9 ;
      RECT 177.16 79.7 177.36 79.9 ;
      RECT 139.49 79.7 139.69 79.9 ;
      RECT 139.09 79.7 139.29 79.9 ;
      RECT 138.69 79.7 138.89 79.9 ;
      RECT 138.29 79.7 138.49 79.9 ;
      RECT 100.62 79.7 100.82 79.9 ;
      RECT 100.22 79.7 100.42 79.9 ;
      RECT 99.82 79.7 100.02 79.9 ;
      RECT 99.42 79.7 99.62 79.9 ;
      RECT 61.75 79.7 61.95 79.9 ;
      RECT 61.35 79.7 61.55 79.9 ;
      RECT 60.95 79.7 61.15 79.9 ;
      RECT 60.55 79.7 60.75 79.9 ;
      RECT 22.88 79.7 23.08 79.9 ;
      RECT 22.48 79.7 22.68 79.9 ;
      RECT 22.08 79.7 22.28 79.9 ;
      RECT 21.68 79.7 21.88 79.9 ;
      RECT 1341.16 69.34 1341.36 69.54 ;
      RECT 1340.76 69.34 1340.96 69.54 ;
      RECT 1340.36 69.34 1340.56 69.54 ;
      RECT 1339.96 69.34 1340.16 69.54 ;
      RECT 1302.29 69.34 1302.49 69.54 ;
      RECT 1301.89 69.34 1302.09 69.54 ;
      RECT 1301.49 69.34 1301.69 69.54 ;
      RECT 1301.09 69.34 1301.29 69.54 ;
      RECT 1263.42 69.34 1263.62 69.54 ;
      RECT 1263.02 69.34 1263.22 69.54 ;
      RECT 1262.62 69.34 1262.82 69.54 ;
      RECT 1262.22 69.34 1262.42 69.54 ;
      RECT 1224.55 69.34 1224.75 69.54 ;
      RECT 1224.15 69.34 1224.35 69.54 ;
      RECT 1223.75 69.34 1223.95 69.54 ;
      RECT 1223.35 69.34 1223.55 69.54 ;
      RECT 1185.68 69.34 1185.88 69.54 ;
      RECT 1185.28 69.34 1185.48 69.54 ;
      RECT 1184.88 69.34 1185.08 69.54 ;
      RECT 1184.48 69.34 1184.68 69.54 ;
      RECT 1146.81 69.34 1147.01 69.54 ;
      RECT 1146.41 69.34 1146.61 69.54 ;
      RECT 1146.01 69.34 1146.21 69.54 ;
      RECT 1145.61 69.34 1145.81 69.54 ;
      RECT 1107.94 69.34 1108.14 69.54 ;
      RECT 1107.54 69.34 1107.74 69.54 ;
      RECT 1107.14 69.34 1107.34 69.54 ;
      RECT 1106.74 69.34 1106.94 69.54 ;
      RECT 1069.07 69.34 1069.27 69.54 ;
      RECT 1068.67 69.34 1068.87 69.54 ;
      RECT 1068.27 69.34 1068.47 69.54 ;
      RECT 1067.87 69.34 1068.07 69.54 ;
      RECT 1030.2 69.34 1030.4 69.54 ;
      RECT 1029.8 69.34 1030 69.54 ;
      RECT 1029.4 69.34 1029.6 69.54 ;
      RECT 1029 69.34 1029.2 69.54 ;
      RECT 991.33 69.34 991.53 69.54 ;
      RECT 990.93 69.34 991.13 69.54 ;
      RECT 990.53 69.34 990.73 69.54 ;
      RECT 990.13 69.34 990.33 69.54 ;
      RECT 952.46 69.34 952.66 69.54 ;
      RECT 952.06 69.34 952.26 69.54 ;
      RECT 951.66 69.34 951.86 69.54 ;
      RECT 951.26 69.34 951.46 69.54 ;
      RECT 408.28 69.34 408.48 69.54 ;
      RECT 407.88 69.34 408.08 69.54 ;
      RECT 407.48 69.34 407.68 69.54 ;
      RECT 407.08 69.34 407.28 69.54 ;
      RECT 369.41 69.34 369.61 69.54 ;
      RECT 369.01 69.34 369.21 69.54 ;
      RECT 368.61 69.34 368.81 69.54 ;
      RECT 368.21 69.34 368.41 69.54 ;
      RECT 330.54 69.34 330.74 69.54 ;
      RECT 330.14 69.34 330.34 69.54 ;
      RECT 329.74 69.34 329.94 69.54 ;
      RECT 329.34 69.34 329.54 69.54 ;
      RECT 291.67 69.34 291.87 69.54 ;
      RECT 291.27 69.34 291.47 69.54 ;
      RECT 290.87 69.34 291.07 69.54 ;
      RECT 290.47 69.34 290.67 69.54 ;
      RECT 252.8 69.34 253 69.54 ;
      RECT 252.4 69.34 252.6 69.54 ;
      RECT 252 69.34 252.2 69.54 ;
      RECT 251.6 69.34 251.8 69.54 ;
      RECT 213.93 69.34 214.13 69.54 ;
      RECT 213.53 69.34 213.73 69.54 ;
      RECT 213.13 69.34 213.33 69.54 ;
      RECT 212.73 69.34 212.93 69.54 ;
      RECT 175.06 69.34 175.26 69.54 ;
      RECT 174.66 69.34 174.86 69.54 ;
      RECT 174.26 69.34 174.46 69.54 ;
      RECT 173.86 69.34 174.06 69.54 ;
      RECT 136.19 69.34 136.39 69.54 ;
      RECT 135.79 69.34 135.99 69.54 ;
      RECT 135.39 69.34 135.59 69.54 ;
      RECT 134.99 69.34 135.19 69.54 ;
      RECT 97.32 69.34 97.52 69.54 ;
      RECT 96.92 69.34 97.12 69.54 ;
      RECT 96.52 69.34 96.72 69.54 ;
      RECT 96.12 69.34 96.32 69.54 ;
      RECT 58.45 69.34 58.65 69.54 ;
      RECT 58.05 69.34 58.25 69.54 ;
      RECT 57.65 69.34 57.85 69.54 ;
      RECT 57.25 69.34 57.45 69.54 ;
      RECT 19.58 69.34 19.78 69.54 ;
      RECT 19.18 69.34 19.38 69.54 ;
      RECT 18.78 69.34 18.98 69.54 ;
      RECT 18.38 69.34 18.58 69.54 ;
      RECT 1341.16 68.94 1341.36 69.14 ;
      RECT 1340.76 68.94 1340.96 69.14 ;
      RECT 1340.36 68.94 1340.56 69.14 ;
      RECT 1339.96 68.94 1340.16 69.14 ;
      RECT 1302.29 68.94 1302.49 69.14 ;
      RECT 1301.89 68.94 1302.09 69.14 ;
      RECT 1301.49 68.94 1301.69 69.14 ;
      RECT 1301.09 68.94 1301.29 69.14 ;
      RECT 1263.42 68.94 1263.62 69.14 ;
      RECT 1263.02 68.94 1263.22 69.14 ;
      RECT 1262.62 68.94 1262.82 69.14 ;
      RECT 1262.22 68.94 1262.42 69.14 ;
      RECT 1224.55 68.94 1224.75 69.14 ;
      RECT 1224.15 68.94 1224.35 69.14 ;
      RECT 1223.75 68.94 1223.95 69.14 ;
      RECT 1223.35 68.94 1223.55 69.14 ;
      RECT 1185.68 68.94 1185.88 69.14 ;
      RECT 1185.28 68.94 1185.48 69.14 ;
      RECT 1184.88 68.94 1185.08 69.14 ;
      RECT 1184.48 68.94 1184.68 69.14 ;
      RECT 1146.81 68.94 1147.01 69.14 ;
      RECT 1146.41 68.94 1146.61 69.14 ;
      RECT 1146.01 68.94 1146.21 69.14 ;
      RECT 1145.61 68.94 1145.81 69.14 ;
      RECT 1107.94 68.94 1108.14 69.14 ;
      RECT 1107.54 68.94 1107.74 69.14 ;
      RECT 1107.14 68.94 1107.34 69.14 ;
      RECT 1106.74 68.94 1106.94 69.14 ;
      RECT 1069.07 68.94 1069.27 69.14 ;
      RECT 1068.67 68.94 1068.87 69.14 ;
      RECT 1068.27 68.94 1068.47 69.14 ;
      RECT 1067.87 68.94 1068.07 69.14 ;
      RECT 1030.2 68.94 1030.4 69.14 ;
      RECT 1029.8 68.94 1030 69.14 ;
      RECT 1029.4 68.94 1029.6 69.14 ;
      RECT 1029 68.94 1029.2 69.14 ;
      RECT 991.33 68.94 991.53 69.14 ;
      RECT 990.93 68.94 991.13 69.14 ;
      RECT 990.53 68.94 990.73 69.14 ;
      RECT 990.13 68.94 990.33 69.14 ;
      RECT 952.46 68.94 952.66 69.14 ;
      RECT 952.06 68.94 952.26 69.14 ;
      RECT 951.66 68.94 951.86 69.14 ;
      RECT 951.26 68.94 951.46 69.14 ;
      RECT 408.28 68.94 408.48 69.14 ;
      RECT 407.88 68.94 408.08 69.14 ;
      RECT 407.48 68.94 407.68 69.14 ;
      RECT 407.08 68.94 407.28 69.14 ;
      RECT 369.41 68.94 369.61 69.14 ;
      RECT 369.01 68.94 369.21 69.14 ;
      RECT 368.61 68.94 368.81 69.14 ;
      RECT 368.21 68.94 368.41 69.14 ;
      RECT 330.54 68.94 330.74 69.14 ;
      RECT 330.14 68.94 330.34 69.14 ;
      RECT 329.74 68.94 329.94 69.14 ;
      RECT 329.34 68.94 329.54 69.14 ;
      RECT 291.67 68.94 291.87 69.14 ;
      RECT 291.27 68.94 291.47 69.14 ;
      RECT 290.87 68.94 291.07 69.14 ;
      RECT 290.47 68.94 290.67 69.14 ;
      RECT 252.8 68.94 253 69.14 ;
      RECT 252.4 68.94 252.6 69.14 ;
      RECT 252 68.94 252.2 69.14 ;
      RECT 251.6 68.94 251.8 69.14 ;
      RECT 213.93 68.94 214.13 69.14 ;
      RECT 213.53 68.94 213.73 69.14 ;
      RECT 213.13 68.94 213.33 69.14 ;
      RECT 212.73 68.94 212.93 69.14 ;
      RECT 175.06 68.94 175.26 69.14 ;
      RECT 174.66 68.94 174.86 69.14 ;
      RECT 174.26 68.94 174.46 69.14 ;
      RECT 173.86 68.94 174.06 69.14 ;
      RECT 136.19 68.94 136.39 69.14 ;
      RECT 135.79 68.94 135.99 69.14 ;
      RECT 135.39 68.94 135.59 69.14 ;
      RECT 134.99 68.94 135.19 69.14 ;
      RECT 97.32 68.94 97.52 69.14 ;
      RECT 96.92 68.94 97.12 69.14 ;
      RECT 96.52 68.94 96.72 69.14 ;
      RECT 96.12 68.94 96.32 69.14 ;
      RECT 58.45 68.94 58.65 69.14 ;
      RECT 58.05 68.94 58.25 69.14 ;
      RECT 57.65 68.94 57.85 69.14 ;
      RECT 57.25 68.94 57.45 69.14 ;
      RECT 19.58 68.94 19.78 69.14 ;
      RECT 19.18 68.94 19.38 69.14 ;
      RECT 18.78 68.94 18.98 69.14 ;
      RECT 18.38 68.94 18.58 69.14 ;
      RECT 1341.16 68.54 1341.36 68.74 ;
      RECT 1340.76 68.54 1340.96 68.74 ;
      RECT 1340.36 68.54 1340.56 68.74 ;
      RECT 1339.96 68.54 1340.16 68.74 ;
      RECT 1302.29 68.54 1302.49 68.74 ;
      RECT 1301.89 68.54 1302.09 68.74 ;
      RECT 1301.49 68.54 1301.69 68.74 ;
      RECT 1301.09 68.54 1301.29 68.74 ;
      RECT 1263.42 68.54 1263.62 68.74 ;
      RECT 1263.02 68.54 1263.22 68.74 ;
      RECT 1262.62 68.54 1262.82 68.74 ;
      RECT 1262.22 68.54 1262.42 68.74 ;
      RECT 1224.55 68.54 1224.75 68.74 ;
      RECT 1224.15 68.54 1224.35 68.74 ;
      RECT 1223.75 68.54 1223.95 68.74 ;
      RECT 1223.35 68.54 1223.55 68.74 ;
      RECT 1185.68 68.54 1185.88 68.74 ;
      RECT 1185.28 68.54 1185.48 68.74 ;
      RECT 1184.88 68.54 1185.08 68.74 ;
      RECT 1184.48 68.54 1184.68 68.74 ;
      RECT 1146.81 68.54 1147.01 68.74 ;
      RECT 1146.41 68.54 1146.61 68.74 ;
      RECT 1146.01 68.54 1146.21 68.74 ;
      RECT 1145.61 68.54 1145.81 68.74 ;
      RECT 1107.94 68.54 1108.14 68.74 ;
      RECT 1107.54 68.54 1107.74 68.74 ;
      RECT 1107.14 68.54 1107.34 68.74 ;
      RECT 1106.74 68.54 1106.94 68.74 ;
      RECT 1069.07 68.54 1069.27 68.74 ;
      RECT 1068.67 68.54 1068.87 68.74 ;
      RECT 1068.27 68.54 1068.47 68.74 ;
      RECT 1067.87 68.54 1068.07 68.74 ;
      RECT 1030.2 68.54 1030.4 68.74 ;
      RECT 1029.8 68.54 1030 68.74 ;
      RECT 1029.4 68.54 1029.6 68.74 ;
      RECT 1029 68.54 1029.2 68.74 ;
      RECT 991.33 68.54 991.53 68.74 ;
      RECT 990.93 68.54 991.13 68.74 ;
      RECT 990.53 68.54 990.73 68.74 ;
      RECT 990.13 68.54 990.33 68.74 ;
      RECT 952.46 68.54 952.66 68.74 ;
      RECT 952.06 68.54 952.26 68.74 ;
      RECT 951.66 68.54 951.86 68.74 ;
      RECT 951.26 68.54 951.46 68.74 ;
      RECT 408.28 68.54 408.48 68.74 ;
      RECT 407.88 68.54 408.08 68.74 ;
      RECT 407.48 68.54 407.68 68.74 ;
      RECT 407.08 68.54 407.28 68.74 ;
      RECT 369.41 68.54 369.61 68.74 ;
      RECT 369.01 68.54 369.21 68.74 ;
      RECT 368.61 68.54 368.81 68.74 ;
      RECT 368.21 68.54 368.41 68.74 ;
      RECT 330.54 68.54 330.74 68.74 ;
      RECT 330.14 68.54 330.34 68.74 ;
      RECT 329.74 68.54 329.94 68.74 ;
      RECT 329.34 68.54 329.54 68.74 ;
      RECT 291.67 68.54 291.87 68.74 ;
      RECT 291.27 68.54 291.47 68.74 ;
      RECT 290.87 68.54 291.07 68.74 ;
      RECT 290.47 68.54 290.67 68.74 ;
      RECT 252.8 68.54 253 68.74 ;
      RECT 252.4 68.54 252.6 68.74 ;
      RECT 252 68.54 252.2 68.74 ;
      RECT 251.6 68.54 251.8 68.74 ;
      RECT 213.93 68.54 214.13 68.74 ;
      RECT 213.53 68.54 213.73 68.74 ;
      RECT 213.13 68.54 213.33 68.74 ;
      RECT 212.73 68.54 212.93 68.74 ;
      RECT 175.06 68.54 175.26 68.74 ;
      RECT 174.66 68.54 174.86 68.74 ;
      RECT 174.26 68.54 174.46 68.74 ;
      RECT 173.86 68.54 174.06 68.74 ;
      RECT 136.19 68.54 136.39 68.74 ;
      RECT 135.79 68.54 135.99 68.74 ;
      RECT 135.39 68.54 135.59 68.74 ;
      RECT 134.99 68.54 135.19 68.74 ;
      RECT 97.32 68.54 97.52 68.74 ;
      RECT 96.92 68.54 97.12 68.74 ;
      RECT 96.52 68.54 96.72 68.74 ;
      RECT 96.12 68.54 96.32 68.74 ;
      RECT 58.45 68.54 58.65 68.74 ;
      RECT 58.05 68.54 58.25 68.74 ;
      RECT 57.65 68.54 57.85 68.74 ;
      RECT 57.25 68.54 57.45 68.74 ;
      RECT 19.58 68.54 19.78 68.74 ;
      RECT 19.18 68.54 19.38 68.74 ;
      RECT 18.78 68.54 18.98 68.74 ;
      RECT 18.38 68.54 18.58 68.74 ;
      RECT 1341.16 68.14 1341.36 68.34 ;
      RECT 1340.76 68.14 1340.96 68.34 ;
      RECT 1340.36 68.14 1340.56 68.34 ;
      RECT 1339.96 68.14 1340.16 68.34 ;
      RECT 1302.29 68.14 1302.49 68.34 ;
      RECT 1301.89 68.14 1302.09 68.34 ;
      RECT 1301.49 68.14 1301.69 68.34 ;
      RECT 1301.09 68.14 1301.29 68.34 ;
      RECT 1263.42 68.14 1263.62 68.34 ;
      RECT 1263.02 68.14 1263.22 68.34 ;
      RECT 1262.62 68.14 1262.82 68.34 ;
      RECT 1262.22 68.14 1262.42 68.34 ;
      RECT 1224.55 68.14 1224.75 68.34 ;
      RECT 1224.15 68.14 1224.35 68.34 ;
      RECT 1223.75 68.14 1223.95 68.34 ;
      RECT 1223.35 68.14 1223.55 68.34 ;
      RECT 1185.68 68.14 1185.88 68.34 ;
      RECT 1185.28 68.14 1185.48 68.34 ;
      RECT 1184.88 68.14 1185.08 68.34 ;
      RECT 1184.48 68.14 1184.68 68.34 ;
      RECT 1146.81 68.14 1147.01 68.34 ;
      RECT 1146.41 68.14 1146.61 68.34 ;
      RECT 1146.01 68.14 1146.21 68.34 ;
      RECT 1145.61 68.14 1145.81 68.34 ;
      RECT 1107.94 68.14 1108.14 68.34 ;
      RECT 1107.54 68.14 1107.74 68.34 ;
      RECT 1107.14 68.14 1107.34 68.34 ;
      RECT 1106.74 68.14 1106.94 68.34 ;
      RECT 1069.07 68.14 1069.27 68.34 ;
      RECT 1068.67 68.14 1068.87 68.34 ;
      RECT 1068.27 68.14 1068.47 68.34 ;
      RECT 1067.87 68.14 1068.07 68.34 ;
      RECT 1030.2 68.14 1030.4 68.34 ;
      RECT 1029.8 68.14 1030 68.34 ;
      RECT 1029.4 68.14 1029.6 68.34 ;
      RECT 1029 68.14 1029.2 68.34 ;
      RECT 991.33 68.14 991.53 68.34 ;
      RECT 990.93 68.14 991.13 68.34 ;
      RECT 990.53 68.14 990.73 68.34 ;
      RECT 990.13 68.14 990.33 68.34 ;
      RECT 952.46 68.14 952.66 68.34 ;
      RECT 952.06 68.14 952.26 68.34 ;
      RECT 951.66 68.14 951.86 68.34 ;
      RECT 951.26 68.14 951.46 68.34 ;
      RECT 408.28 68.14 408.48 68.34 ;
      RECT 407.88 68.14 408.08 68.34 ;
      RECT 407.48 68.14 407.68 68.34 ;
      RECT 407.08 68.14 407.28 68.34 ;
      RECT 369.41 68.14 369.61 68.34 ;
      RECT 369.01 68.14 369.21 68.34 ;
      RECT 368.61 68.14 368.81 68.34 ;
      RECT 368.21 68.14 368.41 68.34 ;
      RECT 330.54 68.14 330.74 68.34 ;
      RECT 330.14 68.14 330.34 68.34 ;
      RECT 329.74 68.14 329.94 68.34 ;
      RECT 329.34 68.14 329.54 68.34 ;
      RECT 291.67 68.14 291.87 68.34 ;
      RECT 291.27 68.14 291.47 68.34 ;
      RECT 290.87 68.14 291.07 68.34 ;
      RECT 290.47 68.14 290.67 68.34 ;
      RECT 252.8 68.14 253 68.34 ;
      RECT 252.4 68.14 252.6 68.34 ;
      RECT 252 68.14 252.2 68.34 ;
      RECT 251.6 68.14 251.8 68.34 ;
      RECT 213.93 68.14 214.13 68.34 ;
      RECT 213.53 68.14 213.73 68.34 ;
      RECT 213.13 68.14 213.33 68.34 ;
      RECT 212.73 68.14 212.93 68.34 ;
      RECT 175.06 68.14 175.26 68.34 ;
      RECT 174.66 68.14 174.86 68.34 ;
      RECT 174.26 68.14 174.46 68.34 ;
      RECT 173.86 68.14 174.06 68.34 ;
      RECT 136.19 68.14 136.39 68.34 ;
      RECT 135.79 68.14 135.99 68.34 ;
      RECT 135.39 68.14 135.59 68.34 ;
      RECT 134.99 68.14 135.19 68.34 ;
      RECT 97.32 68.14 97.52 68.34 ;
      RECT 96.92 68.14 97.12 68.34 ;
      RECT 96.52 68.14 96.72 68.34 ;
      RECT 96.12 68.14 96.32 68.34 ;
      RECT 58.45 68.14 58.65 68.34 ;
      RECT 58.05 68.14 58.25 68.34 ;
      RECT 57.65 68.14 57.85 68.34 ;
      RECT 57.25 68.14 57.45 68.34 ;
      RECT 19.58 68.14 19.78 68.34 ;
      RECT 19.18 68.14 19.38 68.34 ;
      RECT 18.78 68.14 18.98 68.34 ;
      RECT 18.38 68.14 18.58 68.34 ;
    LAYER nwell ;
      RECT 0 0 1378.16 225.76 ;
    LAYER pwell ;
      RECT 0 0 1378.16 225.76 ;
    LAYER OVERLAP ;
      POLYGON 0 0 0 225.76 1378.16 225.76 1378.16 0 ;
  END
  PROPERTY achieved_target_routing_density 0.81 ;
  PROPERTY expanded_util 0.645 ;
END tt_um_not_so_tiny_sparse_acc_ramzxc

END LIBRARY
